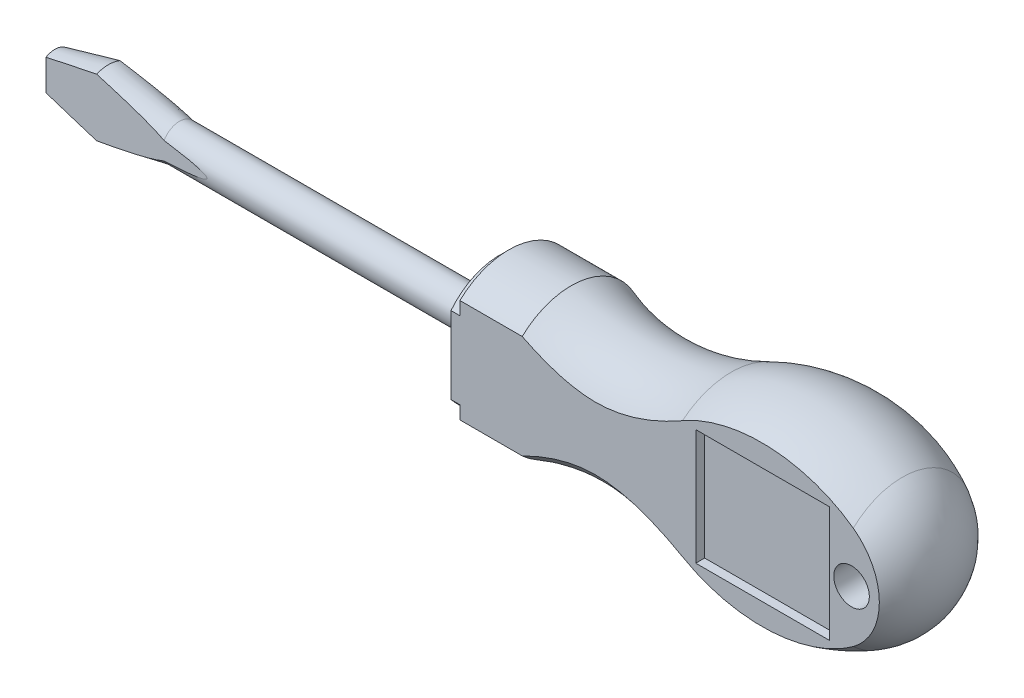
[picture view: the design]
ISO-10303-21;
HEADER;
FILE_DESCRIPTION(('STEP AP214'),'2;1');
FILE_NAME('part.step','',(''),(''),'','','');
FILE_SCHEMA(('AUTOMOTIVE_DESIGN { 1 0 10303 214 1 1 1 1 }'));
ENDSEC;
DATA;
#1=APPLICATION_CONTEXT('core data for automotive mechanical design processes');
#2=APPLICATION_PROTOCOL_DEFINITION('international standard','automotive_design',2000,#1);
#3=PRODUCT_CONTEXT('',#1,'mechanical');
#4=PRODUCT('Part','Part','',(#3));
#5=PRODUCT_RELATED_PRODUCT_CATEGORY('part','',(#4));
#6=PRODUCT_DEFINITION_FORMATION('','',#4);
#7=PRODUCT_DEFINITION_CONTEXT('part definition',#1,'design');
#8=PRODUCT_DEFINITION('design','',#6,#7);
#9=PRODUCT_DEFINITION_SHAPE('','',#8);
#10=(LENGTH_UNIT() NAMED_UNIT(*) SI_UNIT(.MILLI.,.METRE.));
#11=(NAMED_UNIT(*) PLANE_ANGLE_UNIT() SI_UNIT($,.RADIAN.));
#12=(NAMED_UNIT(*) SI_UNIT($,.STERADIAN.) SOLID_ANGLE_UNIT());
#13=UNCERTAINTY_MEASURE_WITH_UNIT(LENGTH_MEASURE(1.E-05),#10,'distance_accuracy_value','');
#14=(GEOMETRIC_REPRESENTATION_CONTEXT(3) GLOBAL_UNCERTAINTY_ASSIGNED_CONTEXT((#13)) GLOBAL_UNIT_ASSIGNED_CONTEXT((#10,
#11,#12)) REPRESENTATION_CONTEXT('',''));
#15=CARTESIAN_POINT('',(0.,0.,0.));
#16=DIRECTION('',(0.,0.,1.));
#17=DIRECTION('',(1.,0.,0.));
#18=AXIS2_PLACEMENT_3D('',#15,#16,#17);
#19=CARTESIAN_POINT('',(-86.,0.,0.));
#20=DIRECTION('',(-1.,0.,0.));
#21=DIRECTION('',(0.,-1.,0.));
#22=AXIS2_PLACEMENT_3D('',#19,#20,#21);
#23=CONICAL_SURFACE('',#22,2.,0.185347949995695);
#24=CARTESIAN_POINT('',(-85.9998,-0.997029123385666,-1.73371939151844));
#25=CARTESIAN_POINT('',(-86.0641111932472,-1.02705859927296,-1.73034898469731));
#26=CARTESIAN_POINT('',(-86.1288400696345,-1.05616798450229,-1.72695668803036));
#27=CARTESIAN_POINT('',(-86.2589632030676,-1.11282617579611,-1.72013722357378));
#28=CARTESIAN_POINT('',(-86.3243573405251,-1.14037525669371,-1.71671006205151));
#29=CARTESIAN_POINT('',(-86.5212414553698,-1.22108563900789,-1.70639180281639));
#30=CARTESIAN_POINT('',(-86.6535075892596,-1.27234401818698,-1.69946002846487));
#31=CARTESIAN_POINT('',(-86.9192182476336,-1.37111150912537,-1.68553472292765));
#32=CARTESIAN_POINT('',(-87.0526610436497,-1.4186253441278,-1.67854128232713));
#33=CARTESIAN_POINT('',(-87.3205297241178,-1.51085295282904,-1.66450287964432));
#34=CARTESIAN_POINT('',(-87.454955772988,-1.5555662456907,-1.65745790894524));
#35=CARTESIAN_POINT('',(-87.7242744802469,-1.64269849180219,-1.64334351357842));
#36=CARTESIAN_POINT('',(-87.8591658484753,-1.68512146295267,-1.63627415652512));
#37=CARTESIAN_POINT('',(-88.1294872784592,-1.76817316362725,-1.62210721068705));
#38=CARTESIAN_POINT('',(-88.2649173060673,-1.80880200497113,-1.61500962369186));
#39=CARTESIAN_POINT('',(-88.6719647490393,-1.92851287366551,-1.59367717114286));
#40=CARTESIAN_POINT('',(-88.9442298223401,-2.00538437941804,-1.57940836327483));
#41=CARTESIAN_POINT('',(-89.6123224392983,-2.18849639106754,-1.54439511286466));
#42=CARTESIAN_POINT('',(-90.0087736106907,-2.2924370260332,-1.52361798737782));
#43=CARTESIAN_POINT('',(-90.8030965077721,-2.49441785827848,-1.48198928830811));
#44=CARTESIAN_POINT('',(-91.2009680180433,-2.59245891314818,-1.46113772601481));
#45=CARTESIAN_POINT('',(-91.9986411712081,-2.78452833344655,-1.41933344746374));
#46=CARTESIAN_POINT('',(-92.3984451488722,-2.8785469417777,-1.39838060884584));
#47=CARTESIAN_POINT('',(-92.998711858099,-3.01718603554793,-1.36692196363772));
#48=CARTESIAN_POINT('',(-93.1989007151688,-3.06300237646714,-1.35643051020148));
#49=CARTESIAN_POINT('',(-93.5994368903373,-3.15392922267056,-1.33543929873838));
#50=CARTESIAN_POINT('',(-93.7997842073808,-3.1990397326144,-1.32493954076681));
#51=CARTESIAN_POINT('',(-94.0002,-3.24384339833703,-1.31443619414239));
#52=B_SPLINE_CURVE_WITH_KNOTS('',3,(#24,#25,#26,#27,#28,#29,#30,#31,#32,#33,#34,#35,#36,#37,#38,
#39,#40,#41,#42,#43,#44,#45,#46,#47,#48,#49,#50,#51),.UNSPECIFIED.,.F.,.F.,(4,2,2,2,2,2,2,2,2,2,
2,2,2,4),(0.,0.213148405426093,0.426259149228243,0.852235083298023,1.27766480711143,
1.70316737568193,2.12789746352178,2.55260104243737,3.40235387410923,4.63341377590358,
5.86429429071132,7.09800838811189,7.71490542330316,8.33179838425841),.UNSPECIFIED.);
#53=CARTESIAN_POINT('',(-86.,-0.997122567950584,-1.73370890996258));
#54=VERTEX_POINT('',#53);
#55=CARTESIAN_POINT('',(-94.,-3.24379868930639,-1.31444667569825));
#56=VERTEX_POINT('',#55);
#57=EDGE_CURVE('E267',#54,#56,#52,.T.);
#58=ORIENTED_EDGE('',*,*,#57,.F.);
#59=CARTESIAN_POINT('',(-86.,0.,0.));
#60=DIRECTION('',(1.,0.,0.));
#61=DIRECTION('',(0.,1.,0.));
#62=AXIS2_PLACEMENT_3D('',#59,#60,#61);
#63=CIRCLE('',#62,2.);
#64=CARTESIAN_POINT('',(-86.,-0.997122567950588,1.73370890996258));
#65=VERTEX_POINT('',#64);
#66=EDGE_CURVE('E347',#65,#54,#63,.T.);
#67=ORIENTED_EDGE('',*,*,#66,.F.);
#68=CARTESIAN_POINT('',(-94.0002,-3.24384339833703,1.31443619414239));
#69=CARTESIAN_POINT('',(-93.7596579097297,-3.19006455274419,1.32704247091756));
#70=CARTESIAN_POINT('',(-93.5192119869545,-3.13585064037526,1.33964370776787));
#71=CARTESIAN_POINT('',(-93.038553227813,-3.02637790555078,1.36483396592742));
#72=CARTESIAN_POINT('',(-92.7983403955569,-2.97111906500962,1.37742298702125));
#73=CARTESIAN_POINT('',(-92.3181143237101,-2.8593643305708,1.40259056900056));
#74=CARTESIAN_POINT('',(-92.0781011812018,-2.80286801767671,1.41516912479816));
#75=CARTESIAN_POINT('',(-91.5984216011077,-2.68842317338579,1.44030806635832));
#76=CARTESIAN_POINT('',(-91.3587551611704,-2.63047465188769,1.4528684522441));
#77=CARTESIAN_POINT('',(-90.8807458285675,-2.5130428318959,1.47791985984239));
#78=CARTESIAN_POINT('',(-90.6424013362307,-2.45356607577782,1.4904109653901));
#79=CARTESIAN_POINT('',(-90.1662557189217,-2.33247168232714,1.51536469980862));
#80=CARTESIAN_POINT('',(-89.9284545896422,-2.27085406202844,1.52782732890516));
#81=CARTESIAN_POINT('',(-89.4535670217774,-2.14492489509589,1.55271513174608));
#82=CARTESIAN_POINT('',(-89.216480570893,-2.08061339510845,1.56514030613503));
#83=CARTESIAN_POINT('',(-88.7432791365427,-1.94850747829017,1.58993974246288));
#84=CARTESIAN_POINT('',(-88.5071641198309,-1.88071318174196,1.60231400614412));
#85=CARTESIAN_POINT('',(-88.0790308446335,-1.75314065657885,1.62475152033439));
#86=CARTESIAN_POINT('',(-87.8867824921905,-1.69413893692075,1.63482682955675));
#87=CARTESIAN_POINT('',(-87.5036598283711,-1.57196725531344,1.65490543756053));
#88=CARTESIAN_POINT('',(-87.3127851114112,-1.50879858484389,1.66490875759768));
#89=CARTESIAN_POINT('',(-87.0278448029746,-1.40959258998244,1.67984184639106));
#90=CARTESIAN_POINT('',(-86.9330171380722,-1.37575256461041,1.68481155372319));
#91=CARTESIAN_POINT('',(-86.7440315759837,-1.30626984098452,1.69471586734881));
#92=CARTESIAN_POINT('',(-86.6498736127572,-1.27062732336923,1.69965047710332));
#93=CARTESIAN_POINT('',(-86.4623264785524,-1.19708852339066,1.7094794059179));
#94=CARTESIAN_POINT('',(-86.3689381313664,-1.15919011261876,1.71437368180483));
#95=CARTESIAN_POINT('',(-86.1833644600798,-1.08047106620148,1.72409918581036));
#96=CARTESIAN_POINT('',(-86.0911795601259,-1.03964943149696,1.72893039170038));
#97=CARTESIAN_POINT('',(-85.9998,-0.997029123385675,1.73371939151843));
#98=B_SPLINE_CURVE_WITH_KNOTS('',3,(#68,#69,#70,#71,#72,#73,#74,#75,#76,#77,#78,#79,#80,#81,#82,
#83,#84,#85,#86,#87,#88,#89,#90,#91,#92,#93,#94,#95,#96,#97),.UNSPECIFIED.,.F.,.F.,(4,2,2,2,2,2,
2,2,2,2,2,2,2,2,4),(0.,0.740408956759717,1.48083074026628,2.22150722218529,2.96217865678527,
3.70008308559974,4.4379816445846,5.17586743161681,5.91372775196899,6.51774967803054,
7.12158526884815,7.42399295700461,7.72637039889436,8.02903779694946,8.33180913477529),.UNSPECIFIED.);
#99=CARTESIAN_POINT('',(-94.,-3.24379868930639,1.31444667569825));
#100=VERTEX_POINT('',#99);
#101=EDGE_CURVE('E203',#100,#65,#98,.T.);
#102=ORIENTED_EDGE('',*,*,#101,.F.);
#103=CARTESIAN_POINT('',(-94.,0.,0.));
#104=DIRECTION('',(1.,0.,0.));
#105=DIRECTION('',(0.,1.,0.));
#106=AXIS2_PLACEMENT_3D('',#103,#104,#105);
#107=CIRCLE('',#106,3.5);
#108=EDGE_CURVE('E343',#100,#56,#107,.T.);
#109=ORIENTED_EDGE('',*,*,#108,.T.);
#110=EDGE_LOOP('',(#58,#67,#102,#109));
#111=FACE_BOUND('',#110,.T.);
#112=ADVANCED_FACE('F38',(#111),#23,.T.);
#113=CARTESIAN_POINT('',(-94.,0.,0.));
#114=DIRECTION('',(1.,0.,0.));
#115=DIRECTION('',(0.,1.,0.));
#116=AXIS2_PLACEMENT_3D('',#113,#114,#115);
#117=CONICAL_SURFACE('',#116,3.5,0.244978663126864);
#118=CARTESIAN_POINT('',(-93.9998,-3.24384839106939,-1.31445715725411));
#119=CARTESIAN_POINT('',(-94.5002347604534,-3.11946254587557,-1.2882304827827));
#120=CARTESIAN_POINT('',(-95.000625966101,-2.99489977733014,-1.26200609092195));
#121=CARTESIAN_POINT('',(-96.001246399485,-2.74513345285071,-1.20956579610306));
#122=CARTESIAN_POINT('',(-96.5014756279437,-2.61992989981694,-1.18334989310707));
#123=CARTESIAN_POINT('',(-97.501703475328,-2.36859351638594,-1.1309301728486));
#124=CARTESIAN_POINT('',(-98.0017020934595,-2.24246068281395,-1.10472635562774));
#125=CARTESIAN_POINT('',(-98.7514105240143,-2.05211247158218,-1.06543580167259));
#126=CARTESIAN_POINT('',(-99.0012656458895,-1.98847143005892,-1.05234144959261));
#127=CARTESIAN_POINT('',(-99.5008423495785,-1.86066442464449,-1.02615974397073));
#128=CARTESIAN_POINT('',(-99.7505639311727,-1.79649845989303,-1.01307239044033));
#129=CARTESIAN_POINT('',(-100.0002,-1.73199912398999,-0.999989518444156));
#130=B_SPLINE_CURVE_WITH_KNOTS('',3,(#118,#119,#120,#121,#122,#123,#124,#125,#126,#127,#128,
#129),.UNSPECIFIED.,.F.,.F.,(4,2,2,2,2,4),(0.,1.54898444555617,3.0979618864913,4.64694462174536,
5.42143947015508,6.19593558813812),.UNSPECIFIED.);
#131=CARTESIAN_POINT('',(-100.,-1.73205080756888,-0.999999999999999));
#132=VERTEX_POINT('',#131);
#133=EDGE_CURVE('E61',#56,#132,#130,.T.);
#134=ORIENTED_EDGE('',*,*,#133,.F.);
#135=ORIENTED_EDGE('',*,*,#108,.F.);
#136=CARTESIAN_POINT('',(-100.0002,-1.73199912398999,0.999989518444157));
#137=CARTESIAN_POINT('',(-99.7407971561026,-1.79902077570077,1.01358424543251));
#138=CARTESIAN_POINT('',(-99.4813023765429,-1.86568392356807,1.02718379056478));
#139=CARTESIAN_POINT('',(-98.9621702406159,-1.99844954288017,1.05439035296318));
#140=CARTESIAN_POINT('',(-98.7025328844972,-2.06455201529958,1.06799737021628));
#141=CARTESIAN_POINT('',(-97.9234699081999,-2.26225266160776,1.10882633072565));
#142=CARTESIAN_POINT('',(-97.4038910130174,-2.39324467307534,1.13605630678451));
#143=CARTESIAN_POINT('',(-96.403625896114,-2.64443239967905,1.1884779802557));
#144=CARTESIAN_POINT('',(-95.9229572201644,-2.7646983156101,1.21366875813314));
#145=CARTESIAN_POINT('',(-94.9614728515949,-3.00464833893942,1.26405801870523));
#146=CARTESIAN_POINT('',(-94.4806571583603,-3.12433244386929,1.28925650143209));
#147=CARTESIAN_POINT('',(-93.9998,-3.24384839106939,1.31445715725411));
#148=B_SPLINE_CURVE_WITH_KNOTS('',3,(#136,#137,#138,#139,#140,#141,#142,#143,#144,#145,#146,
#147),.UNSPECIFIED.,.F.,.F.,(4,2,2,2,2,4),(0.,0.804796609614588,1.60959181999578,
3.21917489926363,4.70755207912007,6.19593556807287),.UNSPECIFIED.);
#149=CARTESIAN_POINT('',(-100.,-1.73205080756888,1.));
#150=VERTEX_POINT('',#149);
#151=EDGE_CURVE('E192',#150,#100,#148,.T.);
#152=ORIENTED_EDGE('',*,*,#151,.F.);
#153=CARTESIAN_POINT('',(-100.,0.,0.));
#154=DIRECTION('',(1.,0.,0.));
#155=DIRECTION('',(0.,1.,0.));
#156=AXIS2_PLACEMENT_3D('',#153,#154,#155);
#157=CIRCLE('',#156,2.);
#158=EDGE_CURVE('E339',#150,#132,#157,.T.);
#159=ORIENTED_EDGE('',*,*,#158,.T.);
#160=EDGE_LOOP('',(#134,#135,#152,#159));
#161=FACE_BOUND('',#160,.T.);
#162=ADVANCED_FACE('F382',(#161),#117,.T.);
#163=CARTESIAN_POINT('',(-9.,0.,0.));
#164=DIRECTION('',(1.,0.,0.));
#165=DIRECTION('',(0.,-1.,0.));
#166=AXIS2_PLACEMENT_3D('',#163,#164,#165);
#167=SPHERICAL_SURFACE('',#166,9.);
#168=CARTESIAN_POINT('',(-4.80330765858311,1.9903045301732,-7.70885602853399));
#169=CARTESIAN_POINT('',(-4.67987699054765,1.97812861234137,-7.64484422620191));
#170=CARTESIAN_POINT('',(-4.5576421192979,1.9544311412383,-7.58058776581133));
#171=CARTESIAN_POINT('',(-4.31850956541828,1.88444434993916,-7.4533214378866));
#172=CARTESIAN_POINT('',(-4.20163401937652,1.83806920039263,-7.39031726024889));
#173=CARTESIAN_POINT('',(-3.97697916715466,1.72318761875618,-7.26771163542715));
#174=CARTESIAN_POINT('',(-3.8692147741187,1.65464575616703,-7.20811581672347));
#175=CARTESIAN_POINT('',(-3.66690742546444,1.49643441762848,-7.09495921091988));
#176=CARTESIAN_POINT('',(-3.57234823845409,1.40679124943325,-7.04139103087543));
#177=CARTESIAN_POINT('',(-3.40676376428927,1.21510191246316,-6.94666826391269));
#178=CARTESIAN_POINT('',(-3.33453799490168,1.11440391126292,-6.90489938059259));
#179=CARTESIAN_POINT('',(-3.20885866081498,0.898527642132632,-6.83170669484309));
#180=CARTESIAN_POINT('',(-3.15538353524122,0.783366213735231,-6.80027101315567));
#181=CARTESIAN_POINT('',(-3.07673416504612,0.559534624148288,-6.75383883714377));
#182=CARTESIAN_POINT('',(-3.04862965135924,0.452244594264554,-6.73714768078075));
#183=CARTESIAN_POINT('',(-3.01057498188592,0.233417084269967,-6.71451668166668));
#184=CARTESIAN_POINT('',(-3.0006079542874,0.121883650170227,-6.70856684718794));
#185=CARTESIAN_POINT('',(-2.99951148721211,-0.0885410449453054,-6.70791228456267));
#186=CARTESIAN_POINT('',(-3.00636627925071,-0.187425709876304,-6.71200424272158));
#187=CARTESIAN_POINT('',(-3.03442671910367,-0.382381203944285,-6.72870585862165));
#188=CARTESIAN_POINT('',(-3.05563115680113,-0.478452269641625,-6.7413147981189));
#189=CARTESIAN_POINT('',(-3.11107629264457,-0.66429396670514,-6.77413263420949));
#190=CARTESIAN_POINT('',(-3.14518792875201,-0.754116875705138,-6.79426626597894));
#191=CARTESIAN_POINT('',(-3.22503287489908,-0.926568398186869,-6.84111172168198));
#192=CARTESIAN_POINT('',(-3.27076935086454,-1.00919504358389,-6.86782533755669));
#193=CARTESIAN_POINT('',(-3.37666625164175,-1.17263374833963,-6.92923867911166));
#194=CARTESIAN_POINT('',(-3.43773100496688,-1.25267340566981,-6.96442874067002));
#195=CARTESIAN_POINT('',(-3.56969281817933,-1.40147200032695,-7.03981280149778));
#196=CARTESIAN_POINT('',(-3.64059436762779,-1.4702257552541,-7.08000908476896));
#197=CARTESIAN_POINT('',(-3.80012285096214,-1.60389738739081,-7.16960509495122));
#198=CARTESIAN_POINT('',(-3.88985563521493,-1.66714830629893,-7.21952158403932));
#199=CARTESIAN_POINT('',(-4.07706172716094,-1.77764123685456,-7.32250983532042));
#200=CARTESIAN_POINT('',(-4.1745390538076,-1.82487486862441,-7.37558323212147));
#201=CARTESIAN_POINT('',(-4.35986983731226,-1.89699324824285,-7.4753631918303));
#202=CARTESIAN_POINT('',(-4.44697267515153,-1.92416797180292,-7.52183016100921));
#203=CARTESIAN_POINT('',(-4.62360194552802,-1.96635493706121,-7.61518387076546));
#204=CARTESIAN_POINT('',(-4.71312258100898,-1.98139399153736,-7.66206945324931));
#205=CARTESIAN_POINT('',(-4.80330765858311,-1.9903045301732,-7.70885602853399));
#206=B_SPLINE_CURVE_WITH_KNOTS('',3,(#168,#169,#170,#171,#172,#173,#174,#175,#176,#177,#178,
#179,#180,#181,#182,#183,#184,#185,#186,#187,#188,#189,#190,#191,#192,#193,#194,#195,#196,#197,
#198,#199,#200,#201,#202,#203,#204,#205),.UNSPECIFIED.,.F.,.F.,(4,2,2,2,2,2,2,2,2,2,2,2,2,2,2,2,
2,2,4),(0.,0.418354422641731,0.838304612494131,1.25892938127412,1.67903249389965,
2.06904704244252,2.45861164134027,2.79315963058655,3.1273962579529,3.42357399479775,
3.71972675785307,4.01299329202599,4.30633978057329,4.62500983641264,4.94382581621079,
5.30418111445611,5.66472465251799,5.97116902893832,6.2769344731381),.UNSPECIFIED.);
#207=CARTESIAN_POINT('',(-4.8031076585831,1.99028475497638,-7.70875225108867));
#208=VERTEX_POINT('',#207);
#209=CARTESIAN_POINT('',(-4.80310765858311,-1.99028475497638,-7.70875225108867));
#210=VERTEX_POINT('',#209);
#211=EDGE_CURVE('E287',#208,#210,#206,.T.);
#212=ORIENTED_EDGE('',*,*,#211,.F.);
#213=CARTESIAN_POINT('',(-4.80310765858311,0.,0.));
#214=DIRECTION('',(1.,0.,0.));
#215=DIRECTION('',(0.,1.,0.));
#216=AXIS2_PLACEMENT_3D('',#213,#214,#215);
#217=CIRCLE('',#216,7.96153846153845);
#218=CARTESIAN_POINT('',(-4.80310765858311,5.75639597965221,5.50000000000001));
#219=VERTEX_POINT('',#218);
#220=EDGE_CURVE('E366',#208,#219,#217,.T.);
#221=ORIENTED_EDGE('',*,*,#220,.T.);
#222=CARTESIAN_POINT('',(-9.,0.,5.50000000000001));
#223=DIRECTION('',(0.,0.,-1.));
#224=DIRECTION('',(-1.,0.,0.));
#225=AXIS2_PLACEMENT_3D('',#222,#223,#224);
#226=CIRCLE('',#225,7.1239034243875);
#227=CARTESIAN_POINT('',(-4.8031076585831,-5.75639597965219,5.50000000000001));
#228=VERTEX_POINT('',#227);
#229=EDGE_CURVE('E309',#228,#219,#226,.F.);
#230=ORIENTED_EDGE('',*,*,#229,.F.);
#231=EDGE_CURVE('E367',#228,#210,#217,.T.);
#232=ORIENTED_EDGE('',*,*,#231,.T.);
#233=EDGE_LOOP('',(#212,#221,#230,#232));
#234=FACE_BOUND('',#233,.T.);
#235=ADVANCED_FACE('F40',(#234),#167,.T.);
#236=CARTESIAN_POINT('',(-15.0621778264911,0.,0.));
#237=DIRECTION('',(1.,0.,0.));
#238=DIRECTION('',(0.,1.,0.));
#239=AXIS2_PLACEMENT_3D('',#236,#237,#238);
#240=DEGENERATE_TOROIDAL_SURFACE('',#239,11.5,22.,.F.);
#241=CARTESIAN_POINT('',(-4.80290765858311,-1.99026495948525,-7.70864847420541));
#242=CARTESIAN_POINT('',(-4.93039350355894,-2.00287079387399,-7.7747636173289));
#243=CARTESIAN_POINT('',(-5.05810757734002,-2.00317192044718,-7.84260432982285));
#244=CARTESIAN_POINT('',(-5.31090760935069,-1.97977019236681,-7.97950600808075));
#245=CARTESIAN_POINT('',(-5.43598940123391,-1.95603183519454,-8.04856863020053));
#246=CARTESIAN_POINT('',(-5.68004785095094,-1.88512174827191,-8.18547613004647));
#247=CARTESIAN_POINT('',(-5.79902430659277,-1.83794924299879,-8.25332096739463));
#248=CARTESIAN_POINT('',(-6.02747074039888,-1.72069036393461,-8.38522576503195));
#249=CARTESIAN_POINT('',(-6.13694262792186,-1.65060860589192,-8.44928648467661));
#250=CARTESIAN_POINT('',(-6.33950166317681,-1.49060737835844,-8.56896216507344));
#251=CARTESIAN_POINT('',(-6.43296987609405,-1.40131732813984,-8.6247672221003));
#252=CARTESIAN_POINT('',(-6.60290209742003,-1.20319442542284,-8.72692036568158));
#253=CARTESIAN_POINT('',(-6.67938491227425,-1.09438343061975,-8.77327890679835));
#254=CARTESIAN_POINT('',(-6.80177168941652,-0.87586283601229,-8.84779506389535));
#255=CARTESIAN_POINT('',(-6.85040259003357,-0.768235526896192,-8.87756073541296));
#256=CARTESIAN_POINT('',(-6.92830335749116,-0.543778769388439,-8.92534936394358));
#257=CARTESIAN_POINT('',(-6.95760071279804,-0.426962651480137,-8.94338899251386));
#258=CARTESIAN_POINT('',(-6.99191512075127,-0.206794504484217,-8.96453132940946));
#259=CARTESIAN_POINT('',(-6.99993416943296,-0.104078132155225,-8.96948045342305));
#260=CARTESIAN_POINT('',(-7.00006490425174,0.101353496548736,-8.96956091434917));
#261=CARTESIAN_POINT('',(-6.99218300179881,0.204068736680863,-8.96469620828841));
#262=CARTESIAN_POINT('',(-6.96200565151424,0.399614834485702,-8.94610318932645));
#263=CARTESIAN_POINT('',(-6.94067586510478,0.492655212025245,-8.93296878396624));
#264=CARTESIAN_POINT('',(-6.88556171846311,0.673494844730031,-8.89911777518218));
#265=CARTESIAN_POINT('',(-6.85177600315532,0.761293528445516,-8.87840034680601));
#266=CARTESIAN_POINT('',(-6.7713163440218,0.933764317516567,-8.82923636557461));
#267=CARTESIAN_POINT('',(-6.72411289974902,1.01809741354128,-8.80047326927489));
#268=CARTESIAN_POINT('',(-6.61939050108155,1.17757674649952,-8.7369658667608));
#269=CARTESIAN_POINT('',(-6.5618675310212,1.25271938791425,-8.70221923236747));
#270=CARTESIAN_POINT('',(-6.43071927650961,1.40143830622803,-8.62346397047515));
#271=CARTESIAN_POINT('',(-6.35598633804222,1.47371132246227,-8.57884279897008));
#272=CARTESIAN_POINT('',(-6.19795808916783,1.60482207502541,-8.48524841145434));
#273=CARTESIAN_POINT('',(-6.11465749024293,1.66365144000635,-8.43627250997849));
#274=CARTESIAN_POINT('',(-5.92896226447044,1.77492807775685,-8.32814505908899));
#275=CARTESIAN_POINT('',(-5.82554564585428,1.8252353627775,-8.26854396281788));
#276=CARTESIAN_POINT('',(-5.61262990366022,1.90727734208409,-8.14746470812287));
#277=CARTESIAN_POINT('',(-5.50312941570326,1.93900785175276,-8.08598613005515));
#278=CARTESIAN_POINT('',(-5.29532642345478,1.98051995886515,-7.97115535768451));
#279=CARTESIAN_POINT('',(-5.197483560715,1.99266848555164,-7.91781536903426));
#280=CARTESIAN_POINT('',(-5.00068300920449,2.00241975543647,-7.8121934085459));
#281=CARTESIAN_POINT('',(-4.90172696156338,2.00004166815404,-7.7599101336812));
#282=CARTESIAN_POINT('',(-4.80290765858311,1.99026495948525,-7.70864847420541));
#283=B_SPLINE_CURVE_WITH_KNOTS('',3,(#241,#242,#243,#244,#245,#246,#247,#248,#249,#250,#251,
#252,#253,#254,#255,#256,#257,#258,#259,#260,#261,#262,#263,#264,#265,#266,#267,#268,#269,#270,
#271,#272,#273,#274,#275,#276,#277,#278,#279,#280,#281,#282),.UNSPECIFIED.,.F.,.F.,(4,2,2,2,2,2,
2,2,2,2,2,2,2,2,2,2,2,2,2,2,4),(0.,0.431852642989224,0.864343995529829,1.29684966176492,
1.72926824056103,2.14923380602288,2.56873203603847,2.93190502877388,3.29456054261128,
3.60236857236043,3.91005251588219,4.19782710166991,4.48563300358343,4.78691799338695,
5.08832047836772,5.42639916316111,5.76468779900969,6.15170567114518,6.53881068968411,
6.87417228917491,7.20909143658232),.UNSPECIFIED.);
#284=EDGE_CURVE('E281',#210,#208,#283,.T.);
#285=ORIENTED_EDGE('',*,*,#284,.F.);
#286=ORIENTED_EDGE('',*,*,#231,.F.);
#287=CARTESIAN_POINT('',(-1.09793778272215,0.,5.50000000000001));
#288=CARTESIAN_POINT('',(-1.09794053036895,0.143185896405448,5.50000000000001));
#289=CARTESIAN_POINT('',(-1.10476981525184,0.28639114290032,5.50000000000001));
#290=CARTESIAN_POINT('',(-1.13182268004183,0.571530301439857,5.50000000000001));
#291=CARTESIAN_POINT('',(-1.15204857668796,0.713463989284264,5.50000000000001));
#292=CARTESIAN_POINT('',(-1.20518507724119,0.995134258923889,5.50000000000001));
#293=CARTESIAN_POINT('',(-1.23811359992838,1.13486744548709,5.50000000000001));
#294=CARTESIAN_POINT('',(-1.31557543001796,1.41110185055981,5.50000000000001));
#295=CARTESIAN_POINT('',(-1.36011544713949,1.54760115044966,5.50000000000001));
#296=CARTESIAN_POINT('',(-1.53928463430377,2.03233731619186,5.50000000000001));
#297=CARTESIAN_POINT('',(-1.7040010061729,2.36977447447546,5.50000000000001));
#298=CARTESIAN_POINT('',(-1.98827681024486,2.85309050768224,5.50000000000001));
#299=CARTESIAN_POINT('',(-2.08942533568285,3.01062036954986,5.50000000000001));
#300=CARTESIAN_POINT('',(-2.3023289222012,3.31839314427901,5.50000000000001));
#301=CARTESIAN_POINT('',(-2.41408262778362,3.46863698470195,5.50000000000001));
#302=CARTESIAN_POINT('',(-2.72272990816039,3.85810294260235,5.50000000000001));
#303=CARTESIAN_POINT('',(-2.92743437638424,4.09112883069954,5.50000000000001));
#304=CARTESIAN_POINT('',(-3.35607613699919,4.5388088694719,5.50000000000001));
#305=CARTESIAN_POINT('',(-3.58002525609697,4.75345155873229,5.50000000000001));
#306=CARTESIAN_POINT('',(-4.04375211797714,5.16552977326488,5.50000000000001));
#307=CARTESIAN_POINT('',(-4.2835524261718,5.36293979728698,5.50000000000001));
#308=CARTESIAN_POINT('',(-4.7759716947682,5.74090055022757,5.50000000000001));
#309=CARTESIAN_POINT('',(-5.02858934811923,5.9214529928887,5.50000000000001));
#310=CARTESIAN_POINT('',(-5.66836726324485,6.34892277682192,5.50000000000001));
#311=CARTESIAN_POINT('',(-6.06200298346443,6.58619324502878,5.50000000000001));
#312=CARTESIAN_POINT('',(-6.86818306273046,7.02621879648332,5.50000000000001));
#313=CARTESIAN_POINT('',(-7.2807354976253,7.22895896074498,5.50000000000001));
#314=CARTESIAN_POINT('',(-8.12090875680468,7.60039402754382,5.50000000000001));
#315=CARTESIAN_POINT('',(-8.54853106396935,7.76908556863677,5.50000000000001));
#316=CARTESIAN_POINT('',(-9.41552557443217,8.07261652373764,5.50000000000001));
#317=CARTESIAN_POINT('',(-9.85489623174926,8.20746036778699,5.50000000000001));
#318=CARTESIAN_POINT('',(-10.7514541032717,8.44576989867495,5.50000000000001));
#319=CARTESIAN_POINT('',(-11.2088218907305,8.54855545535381,5.50000000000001));
#320=CARTESIAN_POINT('',(-12.1301733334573,8.7190629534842,5.50000000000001));
#321=CARTESIAN_POINT('',(-12.594158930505,8.78677437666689,5.50000000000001));
#322=CARTESIAN_POINT('',(-13.5258412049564,8.88706009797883,5.50000000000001));
#323=CARTESIAN_POINT('',(-13.9935373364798,8.91963947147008,5.50000000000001));
#324=CARTESIAN_POINT('',(-14.9300795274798,8.94966440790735,5.50000000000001));
#325=CARTESIAN_POINT('',(-15.3989256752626,8.94710718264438,5.50000000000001));
#326=CARTESIAN_POINT('',(-16.3886802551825,8.90454698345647,5.50000000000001));
#327=CARTESIAN_POINT('',(-16.909411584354,8.86029564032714,5.50000000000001));
#328=CARTESIAN_POINT('',(-17.945152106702,8.72819706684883,5.50000000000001));
#329=CARTESIAN_POINT('',(-18.4601630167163,8.64036329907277,5.50000000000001));
#330=CARTESIAN_POINT('',(-19.4811801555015,8.42106121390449,5.50000000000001));
#331=CARTESIAN_POINT('',(-19.987180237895,8.28956423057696,5.50000000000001));
#332=CARTESIAN_POINT('',(-20.9857023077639,7.98292860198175,5.50000000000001));
#333=CARTESIAN_POINT('',(-21.4782282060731,7.80780277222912,5.50000000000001));
#334=CARTESIAN_POINT('',(-22.3338554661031,7.45913765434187,5.50000000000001));
#335=CARTESIAN_POINT('',(-22.7006202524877,7.29453788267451,5.50000000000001));
#336=CARTESIAN_POINT('',(-23.4212896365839,6.93906334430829,5.50000000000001));
#337=CARTESIAN_POINT('',(-23.7751933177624,6.74818670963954,5.50000000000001));
#338=CARTESIAN_POINT('',(-24.4666049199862,6.34007755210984,5.50000000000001));
#339=CARTESIAN_POINT('',(-24.8041422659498,6.12289498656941,5.50000000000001));
#340=CARTESIAN_POINT('',(-25.4598504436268,5.66111521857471,5.50000000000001));
#341=CARTESIAN_POINT('',(-25.7780315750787,5.41653279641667,5.50000000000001));
#342=CARTESIAN_POINT('',(-26.256493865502,5.01160874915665,5.50000000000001));
#343=CARTESIAN_POINT('',(-26.4251114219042,4.86105712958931,5.50000000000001));
#344=CARTESIAN_POINT('',(-26.7533516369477,4.55046817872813,5.50000000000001));
#345=CARTESIAN_POINT('',(-26.9129764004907,4.39043308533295,5.50000000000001));
#346=CARTESIAN_POINT('',(-27.221637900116,4.06051360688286,5.50000000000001));
#347=CARTESIAN_POINT('',(-27.3706777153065,3.89063211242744,5.50000000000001));
#348=CARTESIAN_POINT('',(-27.6561388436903,3.54056092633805,5.50000000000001));
#349=CARTESIAN_POINT('',(-27.7925633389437,3.36037385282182,5.50000000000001));
#350=CARTESIAN_POINT('',(-28.0167913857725,3.03726706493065,5.50000000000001));
#351=CARTESIAN_POINT('',(-28.1080506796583,2.89674551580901,5.50000000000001));
#352=CARTESIAN_POINT('',(-28.2807412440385,2.60971862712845,5.50000000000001));
#353=CARTESIAN_POINT('',(-28.3621711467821,2.46321245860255,5.50000000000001));
#354=CARTESIAN_POINT('',(-28.5133884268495,2.16458475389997,5.50000000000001));
#355=CARTESIAN_POINT('',(-28.5831952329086,2.01247311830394,5.50000000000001));
#356=CARTESIAN_POINT('',(-28.7094229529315,1.70280721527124,5.50000000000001));
#357=CARTESIAN_POINT('',(-28.7658497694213,1.54525538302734,5.50000000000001));
#358=CARTESIAN_POINT('',(-28.853127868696,1.25908896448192,5.50000000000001));
#359=CARTESIAN_POINT('',(-28.8868619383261,1.13135253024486,5.50000000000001));
#360=CARTESIAN_POINT('',(-28.9438755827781,0.873610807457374,5.50000000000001));
#361=CARTESIAN_POINT('',(-28.9671603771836,0.743606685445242,5.50000000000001));
#362=CARTESIAN_POINT('',(-29.0025794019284,0.482182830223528,5.50000000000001));
#363=CARTESIAN_POINT('',(-29.0147225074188,0.350764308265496,5.50000000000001));
#364=CARTESIAN_POINT('',(-29.0274920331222,0.0873619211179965,5.50000000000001));
#365=CARTESIAN_POINT('',(-29.0281182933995,-0.0446219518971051,5.50000000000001));
#366=CARTESIAN_POINT('',(-29.0178311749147,-0.308153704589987,5.50000000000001));
#367=CARTESIAN_POINT('',(-29.0069162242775,-0.439701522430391,5.50000000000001));
#368=CARTESIAN_POINT('',(-28.9739066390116,-0.701372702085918,5.50000000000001));
#369=CARTESIAN_POINT('',(-28.9518120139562,-0.831496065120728,5.50000000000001));
#370=CARTESIAN_POINT('',(-28.8970854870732,-1.08963404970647,5.50000000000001));
#371=CARTESIAN_POINT('',(-28.8644431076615,-1.21764644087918,5.50000000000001));
#372=CARTESIAN_POINT('',(-28.7895029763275,-1.47083268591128,5.50000000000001));
#373=CARTESIAN_POINT('',(-28.7472002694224,-1.59600504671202,5.50000000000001));
#374=CARTESIAN_POINT('',(-28.5671961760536,-2.07255000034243,5.50000000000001));
#375=CARTESIAN_POINT('',(-28.3981833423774,-2.41246063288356,5.50000000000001));
#376=CARTESIAN_POINT('',(-28.1072496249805,-2.89903362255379,5.50000000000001));
#377=CARTESIAN_POINT('',(-28.0038200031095,-3.0576018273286,5.50000000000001));
#378=CARTESIAN_POINT('',(-27.786302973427,-3.36730008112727,5.50000000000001));
#379=CARTESIAN_POINT('',(-27.6722172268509,-3.5184312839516,5.50000000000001));
#380=CARTESIAN_POINT('',(-27.3572597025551,-3.91016187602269,5.50000000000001));
#381=CARTESIAN_POINT('',(-27.1485361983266,-4.14444166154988,5.50000000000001));
#382=CARTESIAN_POINT('',(-26.7117680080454,-4.59429000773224,5.50000000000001));
#383=CARTESIAN_POINT('',(-26.4837113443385,-4.809846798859,5.50000000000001));
#384=CARTESIAN_POINT('',(-26.0117069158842,-5.22341302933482,5.50000000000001));
#385=CARTESIAN_POINT('',(-25.7677374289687,-5.42139757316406,5.50000000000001));
#386=CARTESIAN_POINT('',(-25.2669234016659,-5.80018191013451,5.50000000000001));
#387=CARTESIAN_POINT('',(-25.0100801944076,-5.98098347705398,5.50000000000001));
#388=CARTESIAN_POINT('',(-24.3620538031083,-6.40716080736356,5.50000000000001));
#389=CARTESIAN_POINT('',(-23.9645083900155,-6.64290714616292,5.50000000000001));
#390=CARTESIAN_POINT('',(-23.1506537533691,-7.07955631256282,5.50000000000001));
#391=CARTESIAN_POINT('',(-22.7343366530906,-7.28044433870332,5.50000000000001));
#392=CARTESIAN_POINT('',(-21.8867894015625,-7.6478183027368,5.50000000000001));
#393=CARTESIAN_POINT('',(-21.4555582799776,-7.81430199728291,5.50000000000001));
#394=CARTESIAN_POINT('',(-20.5815009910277,-8.11305412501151,5.50000000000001));
#395=CARTESIAN_POINT('',(-20.1386763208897,-8.24532695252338,5.50000000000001));
#396=CARTESIAN_POINT('',(-19.2357482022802,-8.47795614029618,5.50000000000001));
#397=CARTESIAN_POINT('',(-18.7754763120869,-8.57765795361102,5.50000000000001));
#398=CARTESIAN_POINT('',(-17.8485419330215,-8.74167002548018,5.50000000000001));
#399=CARTESIAN_POINT('',(-17.3818775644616,-8.80596963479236,5.50000000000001));
#400=CARTESIAN_POINT('',(-16.4450739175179,-8.89910581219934,5.50000000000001));
#401=CARTESIAN_POINT('',(-15.9749349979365,-8.92794599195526,5.50000000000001));
#402=CARTESIAN_POINT('',(-15.0337956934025,-8.95016232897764,5.50000000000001));
#403=CARTESIAN_POINT('',(-14.5627952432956,-8.94353568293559,5.50000000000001));
#404=CARTESIAN_POINT('',(-13.5707624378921,-8.89212467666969,5.50000000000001));
#405=CARTESIAN_POINT('',(-13.049938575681,-8.84321433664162,5.50000000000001));
#406=CARTESIAN_POINT('',(-12.0144224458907,-8.70171856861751,5.50000000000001));
#407=CARTESIAN_POINT('',(-11.4997283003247,-8.60914688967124,5.50000000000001));
#408=CARTESIAN_POINT('',(-10.4798186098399,-8.38029037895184,5.50000000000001));
#409=CARTESIAN_POINT('',(-9.97460878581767,-8.24398000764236,5.50000000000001));
#410=CARTESIAN_POINT('',(-8.9781518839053,-7.92762861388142,5.50000000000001));
#411=CARTESIAN_POINT('',(-8.48690054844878,-7.74760108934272,5.50000000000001));
#412=CARTESIAN_POINT('',(-7.63958555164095,-7.3924867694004,5.50000000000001));
#413=CARTESIAN_POINT('',(-7.27957995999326,-7.22675052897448,5.50000000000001));
#414=CARTESIAN_POINT('',(-6.57238829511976,-6.86969270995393,5.50000000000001));
#415=CARTESIAN_POINT('',(-6.22520307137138,-6.67836943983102,5.50000000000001));
#416=CARTESIAN_POINT('',(-5.54711975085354,-6.27003918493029,5.50000000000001));
#417=CARTESIAN_POINT('',(-5.21619273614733,-6.05308032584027,5.50000000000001));
#418=CARTESIAN_POINT('',(-4.57357386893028,-5.59241001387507,5.50000000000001));
#419=CARTESIAN_POINT('',(-4.26187183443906,-5.34871291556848,5.50000000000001));
#420=CARTESIAN_POINT('',(-3.79300125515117,-4.94534383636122,5.50000000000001));
#421=CARTESIAN_POINT('',(-3.62757402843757,-4.79521428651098,5.50000000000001));
#422=CARTESIAN_POINT('',(-3.30570051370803,-4.48564335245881,5.50000000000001));
#423=CARTESIAN_POINT('',(-3.14925194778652,-4.32620435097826,5.50000000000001));
#424=CARTESIAN_POINT('',(-2.84691828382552,-3.99764811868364,5.50000000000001));
#425=CARTESIAN_POINT('',(-2.70103054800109,-3.82853332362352,5.50000000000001));
#426=CARTESIAN_POINT('',(-2.4218550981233,-3.48018924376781,5.50000000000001));
#427=CARTESIAN_POINT('',(-2.28856408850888,-3.30096262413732,5.50000000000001));
#428=CARTESIAN_POINT('',(-2.06963565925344,-2.97953340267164,5.50000000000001));
#429=CARTESIAN_POINT('',(-1.98056182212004,-2.83967135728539,5.50000000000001));
#430=CARTESIAN_POINT('',(-1.8122482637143,-2.55410351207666,5.50000000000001));
#431=CARTESIAN_POINT('',(-1.73300874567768,-2.40839759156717,5.50000000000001));
#432=CARTESIAN_POINT('',(-1.58617028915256,-2.11157763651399,5.50000000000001));
#433=CARTESIAN_POINT('',(-1.51854747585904,-1.96047548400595,5.50000000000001));
#434=CARTESIAN_POINT('',(-1.39660482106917,-1.65299544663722,5.50000000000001));
#435=CARTESIAN_POINT('',(-1.34227966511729,-1.49661969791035,5.50000000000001));
#436=CARTESIAN_POINT('',(-1.26356627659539,-1.2294920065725,5.50000000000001));
#437=CARTESIAN_POINT('',(-1.23514124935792,-1.11992076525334,5.50000000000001));
#438=CARTESIAN_POINT('',(-1.18594868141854,-0.899079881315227,5.50000000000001));
#439=CARTESIAN_POINT('',(-1.16517960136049,-0.787810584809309,5.50000000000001));
#440=CARTESIAN_POINT('',(-1.13175634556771,-0.56408764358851,5.50000000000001));
#441=CARTESIAN_POINT('',(-1.11909967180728,-0.451634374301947,5.50000000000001));
#442=CARTESIAN_POINT('',(-1.10219023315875,-0.226124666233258,5.50000000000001));
#443=CARTESIAN_POINT('',(-1.09793561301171,-0.113068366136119,5.50000000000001));
#444=CARTESIAN_POINT('',(-1.09793778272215,0.,5.50000000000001));
#445=B_SPLINE_CURVE_WITH_KNOTS('',3,(#287,#288,#289,#290,#291,#292,#293,#294,#295,#296,#297,
#298,#299,#300,#301,#302,#303,#304,#305,#306,#307,#308,#309,#310,#311,#312,#313,#314,#315,#316,
#317,#318,#319,#320,#321,#322,#323,#324,#325,#326,#327,#328,#329,#330,#331,#332,#333,#334,#335,
#336,#337,#338,#339,#340,#341,#342,#343,#344,#345,#346,#347,#348,#349,#350,#351,#352,#353,#354,
#355,#356,#357,#358,#359,#360,#361,#362,#363,#364,#365,#366,#367,#368,#369,#370,#371,#372,#373,
#374,#375,#376,#377,#378,#379,#380,#381,#382,#383,#384,#385,#386,#387,#388,#389,#390,#391,#392,
#393,#394,#395,#396,#397,#398,#399,#400,#401,#402,#403,#404,#405,#406,#407,#408,#409,#410,#411,
#412,#413,#414,#415,#416,#417,#418,#419,#420,#421,#422,#423,#424,#425,#426,#427,#428,#429,#430,
#431,#432,#433,#434,#435,#436,#437,#438,#439,#440,#441,#442,#443,#444),.UNSPECIFIED.,.T.,.F.,(4,
2,2,2,2,2,2,2,2,2,2,2,2,2,2,2,2,2,2,2,2,2,2,2,2,2,2,2,2,2,2,2,2,2,2,2,2,2,2,2,2,2,2,2,2,2,2,2,2,
2,2,2,2,2,2,2,2,2,2,2,2,2,2,2,2,2,2,2,2,2,2,2,2,2,2,2,2,2,4),(0.,0.429431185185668,
0.858936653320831,1.2890502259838,1.71941289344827,2.83862650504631,3.4000131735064,
3.96132818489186,4.89040151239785,5.82004993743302,6.75105154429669,7.68195840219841,
9.05885282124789,10.43634063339,11.8139643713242,13.1914077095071,14.5963485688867,
16.0017105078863,17.4068693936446,18.812139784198,20.3780984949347,21.9435737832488,
23.510078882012,25.0761243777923,26.2811818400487,27.4863250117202,28.6892143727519,
29.8914579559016,30.569291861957,31.2469664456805,31.9244430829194,32.6017483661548,
33.1040760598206,33.6064735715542,34.1080226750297,34.6093501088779,35.0053054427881,
35.401062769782,35.7965045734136,36.1919518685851,36.5874530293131,36.9829538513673,
37.378848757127,37.7749471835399,38.9063767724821,39.4741007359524,40.0417363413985,
40.9816028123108,41.9220558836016,42.8638207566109,43.8054883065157,45.1900988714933,
46.5752959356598,47.9605832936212,49.3456926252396,50.7571334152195,52.1689985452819,
53.5807198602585,54.9925527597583,56.5600263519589,58.1270066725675,59.6949036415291,
61.2623171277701,62.4503578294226,63.6384771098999,64.8244003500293,66.0096900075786,
66.6795660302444,67.3492713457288,68.0188088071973,68.6881706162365,69.1852881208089,
69.6824158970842,70.1785094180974,70.6744043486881,71.0137572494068,71.3530418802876,
71.6922219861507,72.0313271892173),.UNSPECIFIED.);
#446=CARTESIAN_POINT('',(-23.9971410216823,-6.61641444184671,5.50000000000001));
#447=VERTEX_POINT('',#446);
#448=EDGE_CURVE('E303',#447,#228,#445,.T.);
#449=ORIENTED_EDGE('',*,*,#448,.F.);
#450=CARTESIAN_POINT('',(-23.9971410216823,0.,0.));
#451=DIRECTION('',(1.,0.,0.));
#452=DIRECTION('',(0.,1.,0.));
#453=AXIS2_PLACEMENT_3D('',#450,#451,#452);
#454=CIRCLE('',#453,8.60389098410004);
#455=CARTESIAN_POINT('',(-23.9971410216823,6.61641444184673,5.50000000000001));
#456=VERTEX_POINT('',#455);
#457=EDGE_CURVE('E363',#447,#456,#454,.T.);
#458=ORIENTED_EDGE('',*,*,#457,.T.);
#459=EDGE_CURVE('E311',#219,#456,#445,.T.);
#460=ORIENTED_EDGE('',*,*,#459,.F.);
#461=ORIENTED_EDGE('',*,*,#220,.F.);
#462=EDGE_LOOP('',(#285,#286,#449,#458,#460,#461));
#463=FACE_BOUND('',#462,.T.);
#464=ADVANCED_FACE('F293',(#463),#240,.F.);
#465=CARTESIAN_POINT('',(-33.7443735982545,0.,0.));
#466=DIRECTION('',(1.,0.,0.));
#467=DIRECTION('',(0.,1.,0.));
#468=AXIS2_PLACEMENT_3D('',#465,#466,#467);
#469=TOROIDAL_SURFACE('',#468,30.5354084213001,24.);
#470=CARTESIAN_POINT('',(-9.98945607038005,33.508120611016,5.50000000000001));
#471=CARTESIAN_POINT('',(-9.93830665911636,33.1482112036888,5.50000000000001));
#472=CARTESIAN_POINT('',(-9.89515712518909,32.7872114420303,5.50000000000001));
#473=CARTESIAN_POINT('',(-9.82487450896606,32.0636701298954,5.50000000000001));
#474=CARTESIAN_POINT('',(-9.79774079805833,31.7011286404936,5.50000000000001));
#475=CARTESIAN_POINT('',(-9.7403995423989,30.6124145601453,5.50000000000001));
#476=CARTESIAN_POINT('',(-9.73420856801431,29.8848467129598,5.50000000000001));
#477=CARTESIAN_POINT('',(-9.78549820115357,28.4339282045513,5.50000000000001));
#478=CARTESIAN_POINT('',(-9.84280858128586,27.7105714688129,5.50000000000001));
#479=CARTESIAN_POINT('',(-9.97553994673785,26.6315156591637,5.50000000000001));
#480=CARTESIAN_POINT('',(-10.0275821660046,26.2728074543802,5.50000000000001));
#481=CARTESIAN_POINT('',(-10.147096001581,25.5578828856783,5.50000000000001));
#482=CARTESIAN_POINT('',(-10.2145712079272,25.2016671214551,5.50000000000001));
#483=CARTESIAN_POINT('',(-10.4344425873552,24.1633765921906,5.50000000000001));
#484=CARTESIAN_POINT('',(-10.6075473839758,23.4855843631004,5.50000000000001));
#485=CARTESIAN_POINT('',(-11.0086029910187,22.1464325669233,5.50000000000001));
#486=CARTESIAN_POINT('',(-11.2365550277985,21.4850733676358,5.50000000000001));
#487=CARTESIAN_POINT('',(-11.6178803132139,20.5085308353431,5.50000000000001));
#488=CARTESIAN_POINT('',(-11.7515815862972,20.185544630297,5.50000000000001));
#489=CARTESIAN_POINT('',(-12.0317743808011,19.5452661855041,5.50000000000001));
#490=CARTESIAN_POINT('',(-12.1782626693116,19.2279725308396,5.50000000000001));
#491=CARTESIAN_POINT('',(-12.6364991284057,18.2851381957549,5.50000000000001));
#492=CARTESIAN_POINT('',(-12.9670313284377,17.6686123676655,5.50000000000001));
#493=CARTESIAN_POINT('',(-13.690329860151,16.4373255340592,5.50000000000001));
#494=CARTESIAN_POINT('',(-14.0851625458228,15.82378270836,5.50000000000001));
#495=CARTESIAN_POINT('',(-14.9223127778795,14.6299848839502,5.50000000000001));
#496=CARTESIAN_POINT('',(-15.3646321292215,14.0497311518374,5.50000000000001));
#497=CARTESIAN_POINT('',(-16.2929163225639,12.9250629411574,5.50000000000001));
#498=CARTESIAN_POINT('',(-16.7788933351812,12.3806585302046,5.50000000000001));
#499=CARTESIAN_POINT('',(-17.7904350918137,11.3298334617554,5.50000000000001));
#500=CARTESIAN_POINT('',(-18.3160036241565,10.8234164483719,5.50000000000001));
#501=CARTESIAN_POINT('',(-19.154167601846,10.0727446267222,5.50000000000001));
#502=CARTESIAN_POINT('',(-19.4543178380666,9.81445346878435,5.50000000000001));
#503=CARTESIAN_POINT('',(-20.0643821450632,9.30983091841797,5.50000000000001));
#504=CARTESIAN_POINT('',(-20.3742940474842,9.06349690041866,5.50000000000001));
#505=CARTESIAN_POINT('',(-21.3181549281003,8.34243859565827,5.50000000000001));
#506=CARTESIAN_POINT('',(-21.9661028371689,7.88577084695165,5.50000000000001));
#507=CARTESIAN_POINT('',(-22.9632121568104,7.23835075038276,5.50000000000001));
#508=CARTESIAN_POINT('',(-23.3002227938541,7.02856581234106,5.50000000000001));
#509=CARTESIAN_POINT('',(-23.9820820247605,6.62216270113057,5.50000000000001));
#510=CARTESIAN_POINT('',(-24.3269297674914,6.4255431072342,5.50000000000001));
#511=CARTESIAN_POINT('',(-25.0240231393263,6.04618877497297,5.50000000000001));
#512=CARTESIAN_POINT('',(-25.376266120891,5.86344917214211,5.50000000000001));
#513=CARTESIAN_POINT('',(-26.0880232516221,5.51280459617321,5.50000000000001));
#514=CARTESIAN_POINT('',(-26.4475365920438,5.34489798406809,5.50000000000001));
#515=CARTESIAN_POINT('',(-27.2296065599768,5.00083955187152,5.50000000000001));
#516=CARTESIAN_POINT('',(-27.6533592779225,4.82738759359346,5.50000000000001));
#517=CARTESIAN_POINT('',(-28.5104162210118,4.50575744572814,5.50000000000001));
#518=CARTESIAN_POINT('',(-28.9437200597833,4.35757823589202,5.50000000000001));
#519=CARTESIAN_POINT('',(-29.8167010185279,4.0926593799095,5.50000000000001));
#520=CARTESIAN_POINT('',(-30.2563140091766,3.97571098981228,5.50000000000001));
#521=CARTESIAN_POINT('',(-31.1439193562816,3.77877092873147,5.50000000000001));
#522=CARTESIAN_POINT('',(-31.5919098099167,3.698770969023,5.50000000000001));
#523=CARTESIAN_POINT('',(-32.2720873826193,3.61115667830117,5.50000000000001));
#524=CARTESIAN_POINT('',(-32.502239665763,3.58728726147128,5.50000000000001));
#525=CARTESIAN_POINT('',(-32.9634935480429,3.55155115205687,5.50000000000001));
#526=CARTESIAN_POINT('',(-33.1945951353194,3.53968430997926,5.50000000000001));
#527=CARTESIAN_POINT('',(-33.657057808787,3.52832833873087,5.50000000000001));
#528=CARTESIAN_POINT('',(-33.8884188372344,3.52883685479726,5.50000000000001));
#529=CARTESIAN_POINT('',(-34.3507822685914,3.54220662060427,5.50000000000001));
#530=CARTESIAN_POINT('',(-34.5817846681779,3.55506798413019,5.50000000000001));
#531=CARTESIAN_POINT('',(-35.0438108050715,3.59283577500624,5.50000000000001));
#532=CARTESIAN_POINT('',(-35.2748302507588,3.61779443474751,5.50000000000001));
#533=CARTESIAN_POINT('',(-35.7353696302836,3.67907740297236,5.50000000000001));
#534=CARTESIAN_POINT('',(-35.964889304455,3.71540362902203,5.50000000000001));
#535=CARTESIAN_POINT('',(-36.6507574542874,3.84014093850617,5.50000000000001));
#536=CARTESIAN_POINT('',(-37.1043020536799,3.94430064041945,5.50000000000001));
#537=CARTESIAN_POINT('',(-37.8707301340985,4.15152566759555,5.50000000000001));
#538=CARTESIAN_POINT('',(-38.1860218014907,4.24603244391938,5.50000000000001));
#539=CARTESIAN_POINT('',(-38.8117937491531,4.44997362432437,5.50000000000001));
#540=CARTESIAN_POINT('',(-39.1222733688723,4.55941005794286,5.50000000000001));
#541=CARTESIAN_POINT('',(-39.7383870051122,4.79137990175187,5.50000000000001));
#542=CARTESIAN_POINT('',(-40.0440193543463,4.91391771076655,5.50000000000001));
#543=CARTESIAN_POINT('',(-40.6503147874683,5.1706589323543,5.50000000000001));
#544=CARTESIAN_POINT('',(-40.9509780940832,5.3048618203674,5.50000000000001));
#545=CARTESIAN_POINT('',(-41.5481299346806,5.58430136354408,5.50000000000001));
#546=CARTESIAN_POINT('',(-41.8446047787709,5.72956723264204,5.50000000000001));
#547=CARTESIAN_POINT('',(-42.432457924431,6.03008635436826,5.50000000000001));
#548=CARTESIAN_POINT('',(-42.7238358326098,6.18534037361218,5.50000000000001));
#549=CARTESIAN_POINT('',(-43.5899217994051,6.66516317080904,5.50000000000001));
#550=CARTESIAN_POINT('',(-44.1568409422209,7.00391473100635,5.50000000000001));
#551=CARTESIAN_POINT('',(-45.3197558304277,7.7498263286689,5.50000000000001));
#552=CARTESIAN_POINT('',(-45.91354673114,8.16041889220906,5.50000000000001));
#553=CARTESIAN_POINT('',(-47.0710896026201,9.02207526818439,5.50000000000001));
#554=CARTESIAN_POINT('',(-47.6348397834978,9.47314148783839,5.50000000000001));
#555=CARTESIAN_POINT('',(-48.7273818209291,10.4133503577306,5.50000000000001));
#556=CARTESIAN_POINT('',(-49.2562528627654,10.9024008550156,5.50000000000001));
#557=CARTESIAN_POINT('',(-50.2766653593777,11.9181027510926,5.50000000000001));
#558=CARTESIAN_POINT('',(-50.7682041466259,12.4447568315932,5.50000000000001));
#559=CARTESIAN_POINT('',(-51.7945248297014,13.6315520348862,5.50000000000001));
#560=CARTESIAN_POINT('',(-52.3212497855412,14.2986928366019,5.50000000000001));
#561=CARTESIAN_POINT('',(-53.3111149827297,15.6789559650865,5.50000000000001));
#562=CARTESIAN_POINT('',(-53.774245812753,16.3920850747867,5.50000000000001));
#563=CARTESIAN_POINT('',(-54.4169372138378,17.4925554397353,5.50000000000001));
#564=CARTESIAN_POINT('',(-54.6226512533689,17.8648343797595,5.50000000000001));
#565=CARTESIAN_POINT('',(-55.0159713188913,18.6188416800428,5.50000000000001));
#566=CARTESIAN_POINT('',(-55.2035787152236,19.0005693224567,5.50000000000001));
#567=CARTESIAN_POINT('',(-55.5599954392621,19.7725757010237,5.50000000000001));
#568=CARTESIAN_POINT('',(-55.7288099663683,20.1628520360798,5.50000000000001));
#569=CARTESIAN_POINT('',(-56.0471624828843,20.9513001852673,5.50000000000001));
#570=CARTESIAN_POINT('',(-56.1966946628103,21.3494743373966,5.50000000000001));
#571=CARTESIAN_POINT('',(-56.5860650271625,22.4697320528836,5.50000000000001));
#572=CARTESIAN_POINT('',(-56.8040789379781,23.1995318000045,5.50000000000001));
#573=CARTESIAN_POINT('',(-57.1738301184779,24.6757048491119,5.50000000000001));
#574=CARTESIAN_POINT('',(-57.3255738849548,25.4220765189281,5.50000000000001));
#575=CARTESIAN_POINT('',(-57.501912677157,26.5486848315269,5.50000000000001));
#576=CARTESIAN_POINT('',(-57.5521246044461,26.9250644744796,5.50000000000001));
#577=CARTESIAN_POINT('',(-57.6353873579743,27.6796512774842,5.50000000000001));
#578=CARTESIAN_POINT('',(-57.66844238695,28.0578579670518,5.50000000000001));
#579=CARTESIAN_POINT('',(-57.7172452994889,28.8152147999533,5.50000000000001));
#580=CARTESIAN_POINT('',(-57.7330008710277,29.1943644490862,5.50000000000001));
#581=CARTESIAN_POINT('',(-57.7471327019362,29.9529739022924,5.50000000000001));
#582=CARTESIAN_POINT('',(-57.7455091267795,30.3324337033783,5.50000000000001));
#583=CARTESIAN_POINT('',(-57.7223906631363,31.1798160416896,5.50000000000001));
#584=CARTESIAN_POINT('',(-57.6963274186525,31.647626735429,5.50000000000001));
#585=CARTESIAN_POINT('',(-57.6373166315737,32.3472349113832,5.50000000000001));
#586=CARTESIAN_POINT('',(-57.6143508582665,32.5799186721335,5.50000000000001));
#587=CARTESIAN_POINT('',(-57.5617911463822,33.0445936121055,5.50000000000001));
#588=CARTESIAN_POINT('',(-57.5321955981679,33.2765846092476,5.50000000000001));
#589=CARTESIAN_POINT('',(-57.4992911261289,33.508120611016,5.50000000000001));
#590=B_SPLINE_CURVE_WITH_KNOTS('',3,(#470,#471,#472,#473,#474,#475,#476,#477,#478,#479,#480,
#481,#482,#483,#484,#485,#486,#487,#488,#489,#490,#491,#492,#493,#494,#495,#496,#497,#498,#499,
#500,#501,#502,#503,#504,#505,#506,#507,#508,#509,#510,#511,#512,#513,#514,#515,#516,#517,#518,
#519,#520,#521,#522,#523,#524,#525,#526,#527,#528,#529,#530,#531,#532,#533,#534,#535,#536,#537,
#538,#539,#540,#541,#542,#543,#544,#545,#546,#547,#548,#549,#550,#551,#552,#553,#554,#555,#556,
#557,#558,#559,#560,#561,#562,#563,#564,#565,#566,#567,#568,#569,#570,#571,#572,#573,#574,#575,
#576,#577,#578,#579,#580,#581,#582,#583,#584,#585,#586,#587,#588,#589),.UNSPECIFIED.,.F.,.F.,(4,
2,2,2,2,2,2,2,2,2,2,2,2,2,2,2,2,2,2,2,2,2,2,2,2,2,2,2,2,2,2,2,2,2,2,2,2,2,2,2,2,2,2,2,2,2,2,2,2,
2,2,2,2,2,2,2,2,2,2,4),(0.,1.09039714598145,2.18075149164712,4.36053739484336,6.53449407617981,
7.62159151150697,8.70894208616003,10.8050697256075,12.9012442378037,13.9496956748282,
14.9978827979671,17.0941549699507,19.2806561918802,21.467240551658,23.6544363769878,
25.8418417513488,27.0295255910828,28.2169474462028,30.5922977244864,31.7829934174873,
32.9735604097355,34.1637082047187,35.3537243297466,36.7266617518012,38.0995437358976,
39.4630057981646,40.826161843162,41.5200551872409,42.2139398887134,42.9076925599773,
43.6014516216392,44.2982331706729,44.9951323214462,46.3892696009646,47.3763880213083,
48.3636407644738,49.351226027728,50.3387669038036,51.3290125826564,52.3193343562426,
54.2991210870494,56.463175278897,58.6273582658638,60.7864456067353,62.9456870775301,
65.4922136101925,68.0391165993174,69.3147152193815,70.5902172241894,71.8653654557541,
73.1408969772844,75.4227246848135,77.7043286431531,78.8431442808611,79.9816808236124,
81.1197111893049,82.2577307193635,83.6624856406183,84.3638485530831,85.0653819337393),.UNSPECIFIED.);
#591=CARTESIAN_POINT('',(-42.,5.80947501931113,5.50000000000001));
#592=VERTEX_POINT('',#591);
#593=EDGE_CURVE('E325',#456,#592,#590,.T.);
#594=ORIENTED_EDGE('',*,*,#593,.F.);
#595=ORIENTED_EDGE('',*,*,#457,.F.);
#596=CARTESIAN_POINT('',(-57.4992911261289,-33.508120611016,5.50000000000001));
#597=CARTESIAN_POINT('',(-57.5504405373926,-33.1482112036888,5.50000000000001));
#598=CARTESIAN_POINT('',(-57.5935900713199,-32.7872114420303,5.50000000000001));
#599=CARTESIAN_POINT('',(-57.6638726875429,-32.0636701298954,5.50000000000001));
#600=CARTESIAN_POINT('',(-57.6910063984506,-31.7011286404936,5.50000000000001));
#601=CARTESIAN_POINT('',(-57.7483476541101,-30.6124145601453,5.50000000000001));
#602=CARTESIAN_POINT('',(-57.7545386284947,-29.8848467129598,5.50000000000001));
#603=CARTESIAN_POINT('',(-57.7032489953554,-28.4339282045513,5.50000000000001));
#604=CARTESIAN_POINT('',(-57.6459386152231,-27.7105714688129,5.50000000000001));
#605=CARTESIAN_POINT('',(-57.5132072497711,-26.6315156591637,5.50000000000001));
#606=CARTESIAN_POINT('',(-57.4611650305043,-26.2728074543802,5.50000000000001));
#607=CARTESIAN_POINT('',(-57.3416511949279,-25.5578828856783,5.50000000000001));
#608=CARTESIAN_POINT('',(-57.2741759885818,-25.2016671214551,5.50000000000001));
#609=CARTESIAN_POINT('',(-57.0543046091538,-24.1633765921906,5.50000000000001));
#610=CARTESIAN_POINT('',(-56.8811998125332,-23.4855843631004,5.50000000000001));
#611=CARTESIAN_POINT('',(-56.4801442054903,-22.1464325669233,5.50000000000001));
#612=CARTESIAN_POINT('',(-56.2521921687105,-21.4850733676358,5.50000000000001));
#613=CARTESIAN_POINT('',(-55.8708668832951,-20.5085308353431,5.50000000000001));
#614=CARTESIAN_POINT('',(-55.7371656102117,-20.185544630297,5.50000000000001));
#615=CARTESIAN_POINT('',(-55.4569728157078,-19.5452661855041,5.50000000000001));
#616=CARTESIAN_POINT('',(-55.3104845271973,-19.2279725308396,5.50000000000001));
#617=CARTESIAN_POINT('',(-54.8522480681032,-18.2851381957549,5.50000000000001));
#618=CARTESIAN_POINT('',(-54.5217158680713,-17.6686123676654,5.50000000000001));
#619=CARTESIAN_POINT('',(-53.7984173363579,-16.4373255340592,5.50000000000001));
#620=CARTESIAN_POINT('',(-53.4035846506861,-15.82378270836,5.50000000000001));
#621=CARTESIAN_POINT('',(-52.5664344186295,-14.6299848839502,5.50000000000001));
#622=CARTESIAN_POINT('',(-52.1241150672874,-14.0497311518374,5.50000000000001));
#623=CARTESIAN_POINT('',(-51.195830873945,-12.9250629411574,5.50000000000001));
#624=CARTESIAN_POINT('',(-50.7098538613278,-12.3806585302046,5.50000000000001));
#625=CARTESIAN_POINT('',(-49.6983121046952,-11.3298334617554,5.50000000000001));
#626=CARTESIAN_POINT('',(-49.1727435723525,-10.8234164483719,5.50000000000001));
#627=CARTESIAN_POINT('',(-48.334579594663,-10.0727446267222,5.50000000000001));
#628=CARTESIAN_POINT('',(-48.0344293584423,-9.81445346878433,5.50000000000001));
#629=CARTESIAN_POINT('',(-47.4243650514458,-9.30983091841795,5.50000000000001));
#630=CARTESIAN_POINT('',(-47.1144531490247,-9.06349690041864,5.50000000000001));
#631=CARTESIAN_POINT('',(-46.1705922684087,-8.34243859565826,5.50000000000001));
#632=CARTESIAN_POINT('',(-45.5226443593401,-7.88577084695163,5.50000000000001));
#633=CARTESIAN_POINT('',(-44.5255350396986,-7.23835075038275,5.50000000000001));
#634=CARTESIAN_POINT('',(-44.1885244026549,-7.02856581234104,5.50000000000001));
#635=CARTESIAN_POINT('',(-43.5066651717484,-6.62216270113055,5.50000000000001));
#636=CARTESIAN_POINT('',(-43.1618174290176,-6.42554310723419,5.50000000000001));
#637=CARTESIAN_POINT('',(-42.4647240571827,-6.04618877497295,5.50000000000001));
#638=CARTESIAN_POINT('',(-42.1124810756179,-5.86344917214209,5.50000000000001));
#639=CARTESIAN_POINT('',(-41.4007239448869,-5.51280459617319,5.50000000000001));
#640=CARTESIAN_POINT('',(-41.0412106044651,-5.34489798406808,5.50000000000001));
#641=CARTESIAN_POINT('',(-40.2591406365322,-5.00083955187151,5.50000000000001));
#642=CARTESIAN_POINT('',(-39.8353879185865,-4.82738759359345,5.50000000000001));
#643=CARTESIAN_POINT('',(-38.9783309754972,-4.50575744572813,5.50000000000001));
#644=CARTESIAN_POINT('',(-38.5450271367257,-4.35757823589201,5.50000000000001));
#645=CARTESIAN_POINT('',(-37.6720461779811,-4.09265937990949,5.50000000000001));
#646=CARTESIAN_POINT('',(-37.2324331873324,-3.97571098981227,5.50000000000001));
#647=CARTESIAN_POINT('',(-36.3448278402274,-3.77877092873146,5.50000000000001));
#648=CARTESIAN_POINT('',(-35.8968373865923,-3.69877096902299,5.50000000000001));
#649=CARTESIAN_POINT('',(-35.2166598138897,-3.61115667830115,5.50000000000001));
#650=CARTESIAN_POINT('',(-34.986507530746,-3.58728726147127,5.50000000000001));
#651=CARTESIAN_POINT('',(-34.5252536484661,-3.55155115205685,5.50000000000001));
#652=CARTESIAN_POINT('',(-34.2941520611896,-3.53968430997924,5.50000000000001));
#653=CARTESIAN_POINT('',(-33.8316893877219,-3.52832833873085,5.50000000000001));
#654=CARTESIAN_POINT('',(-33.6003283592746,-3.52883685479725,5.50000000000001));
#655=CARTESIAN_POINT('',(-33.1379649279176,-3.54220662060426,5.50000000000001));
#656=CARTESIAN_POINT('',(-32.9069625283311,-3.55506798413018,5.50000000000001));
#657=CARTESIAN_POINT('',(-32.4449363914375,-3.59283577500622,5.50000000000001));
#658=CARTESIAN_POINT('',(-32.2139169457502,-3.6177944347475,5.50000000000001));
#659=CARTESIAN_POINT('',(-31.7533775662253,-3.67907740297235,5.50000000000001));
#660=CARTESIAN_POINT('',(-31.523857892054,-3.71540362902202,5.50000000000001));
#661=CARTESIAN_POINT('',(-30.8379897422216,-3.84014093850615,5.50000000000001));
#662=CARTESIAN_POINT('',(-30.3844451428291,-3.94430064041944,5.50000000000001));
#663=CARTESIAN_POINT('',(-29.6180170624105,-4.15152566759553,5.50000000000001));
#664=CARTESIAN_POINT('',(-29.3027253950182,-4.24603244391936,5.50000000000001));
#665=CARTESIAN_POINT('',(-28.6769534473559,-4.44997362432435,5.50000000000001));
#666=CARTESIAN_POINT('',(-28.3664738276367,-4.55941005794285,5.50000000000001));
#667=CARTESIAN_POINT('',(-27.7503601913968,-4.79137990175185,5.50000000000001));
#668=CARTESIAN_POINT('',(-27.4447278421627,-4.91391771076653,5.50000000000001));
#669=CARTESIAN_POINT('',(-26.8384324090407,-5.17065893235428,5.50000000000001));
#670=CARTESIAN_POINT('',(-26.5377691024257,-5.30486182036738,5.50000000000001));
#671=CARTESIAN_POINT('',(-25.9406172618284,-5.58430136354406,5.50000000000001));
#672=CARTESIAN_POINT('',(-25.6441424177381,-5.72956723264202,5.50000000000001));
#673=CARTESIAN_POINT('',(-25.056289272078,-6.03008635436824,5.50000000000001));
#674=CARTESIAN_POINT('',(-24.7649113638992,-6.18534037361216,5.50000000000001));
#675=CARTESIAN_POINT('',(-23.8988253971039,-6.66516317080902,5.50000000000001));
#676=CARTESIAN_POINT('',(-23.3319062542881,-7.00391473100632,5.50000000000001));
#677=CARTESIAN_POINT('',(-22.1689913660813,-7.74982632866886,5.50000000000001));
#678=CARTESIAN_POINT('',(-21.5752004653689,-8.16041889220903,5.50000000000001));
#679=CARTESIAN_POINT('',(-20.4176575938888,-9.02207526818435,5.50000000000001));
#680=CARTESIAN_POINT('',(-19.8539074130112,-9.47314148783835,5.50000000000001));
#681=CARTESIAN_POINT('',(-18.7613653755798,-10.4133503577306,5.50000000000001));
#682=CARTESIAN_POINT('',(-18.2324943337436,-10.9024008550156,5.50000000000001));
#683=CARTESIAN_POINT('',(-17.2120818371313,-11.9181027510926,5.50000000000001));
#684=CARTESIAN_POINT('',(-16.7205430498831,-12.4447568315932,5.50000000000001));
#685=CARTESIAN_POINT('',(-15.6942223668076,-13.6315520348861,5.50000000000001));
#686=CARTESIAN_POINT('',(-15.1674974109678,-14.2986928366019,5.50000000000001));
#687=CARTESIAN_POINT('',(-14.1776322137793,-15.6789559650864,5.50000000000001));
#688=CARTESIAN_POINT('',(-13.714501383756,-16.3920850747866,5.50000000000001));
#689=CARTESIAN_POINT('',(-13.0718099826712,-17.4925554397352,5.50000000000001));
#690=CARTESIAN_POINT('',(-12.8660959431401,-17.8648343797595,5.50000000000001));
#691=CARTESIAN_POINT('',(-12.4727758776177,-18.6188416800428,5.50000000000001));
#692=CARTESIAN_POINT('',(-12.2851684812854,-19.0005693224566,5.50000000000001));
#693=CARTESIAN_POINT('',(-11.9287517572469,-19.7725757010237,5.50000000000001));
#694=CARTESIAN_POINT('',(-11.7599372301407,-20.1628520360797,5.50000000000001));
#695=CARTESIAN_POINT('',(-11.4415847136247,-20.9513001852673,5.50000000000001));
#696=CARTESIAN_POINT('',(-11.2920525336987,-21.3494743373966,5.50000000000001));
#697=CARTESIAN_POINT('',(-10.9026821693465,-22.4697320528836,5.50000000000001));
#698=CARTESIAN_POINT('',(-10.6846682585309,-23.1995318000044,5.50000000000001));
#699=CARTESIAN_POINT('',(-10.314917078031,-24.6757048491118,5.50000000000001));
#700=CARTESIAN_POINT('',(-10.1631733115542,-25.4220765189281,5.50000000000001));
#701=CARTESIAN_POINT('',(-9.98683451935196,-26.5486848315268,5.50000000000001));
#702=CARTESIAN_POINT('',(-9.93662259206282,-26.9250644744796,5.50000000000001));
#703=CARTESIAN_POINT('',(-9.85335983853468,-27.6796512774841,5.50000000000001));
#704=CARTESIAN_POINT('',(-9.82030480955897,-28.0578579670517,5.50000000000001));
#705=CARTESIAN_POINT('',(-9.77150189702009,-28.8152147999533,5.50000000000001));
#706=CARTESIAN_POINT('',(-9.75574632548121,-29.1943644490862,5.50000000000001));
#707=CARTESIAN_POINT('',(-9.7416144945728,-29.9529739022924,5.50000000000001));
#708=CARTESIAN_POINT('',(-9.74323806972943,-30.3324337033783,5.50000000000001));
#709=CARTESIAN_POINT('',(-9.76635653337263,-31.1798160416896,5.50000000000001));
#710=CARTESIAN_POINT('',(-9.79241977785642,-31.6476267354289,5.50000000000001));
#711=CARTESIAN_POINT('',(-9.85143056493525,-32.3472349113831,5.50000000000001));
#712=CARTESIAN_POINT('',(-9.8743963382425,-32.5799186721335,5.50000000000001));
#713=CARTESIAN_POINT('',(-9.9269560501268,-33.0445936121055,5.50000000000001));
#714=CARTESIAN_POINT('',(-9.95655159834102,-33.2765846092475,5.50000000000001));
#715=CARTESIAN_POINT('',(-9.98945607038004,-33.508120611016,5.50000000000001));
#716=B_SPLINE_CURVE_WITH_KNOTS('',3,(#596,#597,#598,#599,#600,#601,#602,#603,#604,#605,#606,
#607,#608,#609,#610,#611,#612,#613,#614,#615,#616,#617,#618,#619,#620,#621,#622,#623,#624,#625,
#626,#627,#628,#629,#630,#631,#632,#633,#634,#635,#636,#637,#638,#639,#640,#641,#642,#643,#644,
#645,#646,#647,#648,#649,#650,#651,#652,#653,#654,#655,#656,#657,#658,#659,#660,#661,#662,#663,
#664,#665,#666,#667,#668,#669,#670,#671,#672,#673,#674,#675,#676,#677,#678,#679,#680,#681,#682,
#683,#684,#685,#686,#687,#688,#689,#690,#691,#692,#693,#694,#695,#696,#697,#698,#699,#700,#701,
#702,#703,#704,#705,#706,#707,#708,#709,#710,#711,#712,#713,#714,#715),.UNSPECIFIED.,.F.,.F.,(4,
2,2,2,2,2,2,2,2,2,2,2,2,2,2,2,2,2,2,2,2,2,2,2,2,2,2,2,2,2,2,2,2,2,2,2,2,2,2,2,2,2,2,2,2,2,2,2,2,
2,2,2,2,2,2,2,2,2,2,4),(0.,1.09039714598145,2.18075149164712,4.36053739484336,6.53449407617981,
7.62159151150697,8.70894208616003,10.8050697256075,12.9012442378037,13.9496956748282,
14.9978827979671,17.0941549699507,19.2806561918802,21.467240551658,23.6544363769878,
25.8418417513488,27.0295255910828,28.2169474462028,30.5922977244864,31.7829934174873,
32.9735604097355,34.1637082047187,35.3537243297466,36.7266617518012,38.0995437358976,
39.4630057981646,40.826161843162,41.5200551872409,42.2139398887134,42.9076925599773,
43.6014516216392,44.2982331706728,44.9951323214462,46.3892696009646,47.3763880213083,
48.3636407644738,49.351226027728,50.3387669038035,51.3290125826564,52.3193343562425,
54.2991210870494,56.4631752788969,58.6273582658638,60.7864456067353,62.94568707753,
65.4922136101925,68.0391165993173,69.3147152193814,70.5902172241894,71.865365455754,
73.1408969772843,75.4227246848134,77.7043286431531,78.843144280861,79.9816808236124,
81.1197111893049,82.2577307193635,83.6624856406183,84.3638485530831,85.0653819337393),.UNSPECIFIED.);
#717=CARTESIAN_POINT('',(-42.,-5.80947501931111,5.50000000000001));
#718=VERTEX_POINT('',#717);
#719=EDGE_CURVE('E310',#718,#447,#716,.T.);
#720=ORIENTED_EDGE('',*,*,#719,.F.);
#721=CARTESIAN_POINT('',(-42.,0.,0.));
#722=DIRECTION('',(1.,0.,0.));
#723=DIRECTION('',(0.,1.,0.));
#724=AXIS2_PLACEMENT_3D('',#721,#722,#723);
#725=CIRCLE('',#724,8.);
#726=EDGE_CURVE('E360',#718,#592,#725,.T.);
#727=ORIENTED_EDGE('',*,*,#726,.T.);
#728=EDGE_LOOP('',(#594,#595,#720,#727));
#729=FACE_BOUND('',#728,.T.);
#730=ADVANCED_FACE('F297',(#729),#469,.F.);
#731=CARTESIAN_POINT('',(-100.,0.,0.));
#732=DIRECTION('',(1.,0.,0.));
#733=DIRECTION('',(0.,1.,0.));
#734=AXIS2_PLACEMENT_3D('',#731,#732,#733);
#735=CYLINDRICAL_SURFACE('',#734,8.);
#736=DIRECTION('',(1.,0.,0.));
#737=VECTOR('',#736,1.);
#738=CARTESIAN_POINT('',(-100.,5.80947501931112,5.50000000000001));
#739=LINE('',#738,#737);
#740=CARTESIAN_POINT('',(-49.,5.80947501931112,5.50000000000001));
#741=VERTEX_POINT('',#740);
#742=EDGE_CURVE('E331',#592,#741,#739,.F.);
#743=ORIENTED_EDGE('',*,*,#742,.F.);
#744=ORIENTED_EDGE('',*,*,#726,.F.);
#745=DIRECTION('',(1.,0.,0.));
#746=VECTOR('',#745,1.);
#747=CARTESIAN_POINT('',(-100.,-5.80947501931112,5.50000000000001));
#748=LINE('',#747,#746);
#749=CARTESIAN_POINT('',(-49.,-5.80947501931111,5.50000000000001));
#750=VERTEX_POINT('',#749);
#751=EDGE_CURVE('E589',#750,#718,#748,.T.);
#752=ORIENTED_EDGE('',*,*,#751,.F.);
#753=CARTESIAN_POINT('',(-49.,0.,0.));
#754=DIRECTION('',(1.,0.,0.));
#755=DIRECTION('',(0.,1.,0.));
#756=AXIS2_PLACEMENT_3D('',#753,#754,#755);
#757=CIRCLE('',#756,7.99999999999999);
#758=EDGE_CURVE('E357',#750,#741,#757,.T.);
#759=ORIENTED_EDGE('',*,*,#758,.T.);
#760=EDGE_LOOP('',(#743,#744,#752,#759));
#761=FACE_BOUND('',#760,.T.);
#762=ADVANCED_FACE('F539',(#761),#735,.T.);
#763=CARTESIAN_POINT('',(-49.,8.,0.));
#764=DIRECTION('',(-1.,0.,0.));
#765=DIRECTION('',(0.,-1.,0.));
#766=AXIS2_PLACEMENT_3D('',#763,#764,#765);
#767=PLANE('',#766);
#768=DIRECTION('',(0.,-1.,0.));
#769=VECTOR('',#768,1.);
#770=CARTESIAN_POINT('',(-49.,8.,5.50000000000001));
#771=LINE('',#770,#769);
#772=CARTESIAN_POINT('',(-49.,4.33012701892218,5.50000000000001));
#773=VERTEX_POINT('',#772);
#774=EDGE_CURVE('E333',#741,#773,#771,.T.);
#775=ORIENTED_EDGE('',*,*,#774,.F.);
#776=ORIENTED_EDGE('',*,*,#758,.F.);
#777=CARTESIAN_POINT('',(-49.,-4.33012701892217,5.50000000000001));
#778=VERTEX_POINT('',#777);
#779=EDGE_CURVE('E586',#778,#750,#771,.T.);
#780=ORIENTED_EDGE('',*,*,#779,.F.);
#781=CARTESIAN_POINT('',(-49.,0.,0.));
#782=DIRECTION('',(1.,0.,0.));
#783=DIRECTION('',(0.,1.,0.));
#784=AXIS2_PLACEMENT_3D('',#781,#782,#783);
#785=CIRCLE('',#784,7.);
#786=EDGE_CURVE('E354',#778,#773,#785,.T.);
#787=ORIENTED_EDGE('',*,*,#786,.T.);
#788=EDGE_LOOP('',(#775,#776,#780,#787));
#789=FACE_BOUND('',#788,.T.);
#790=ADVANCED_FACE('F406',(#789),#767,.T.);
#791=CARTESIAN_POINT('',(-100.,0.,0.));
#792=DIRECTION('',(1.,0.,0.));
#793=DIRECTION('',(0.,1.,0.));
#794=AXIS2_PLACEMENT_3D('',#791,#792,#793);
#795=CYLINDRICAL_SURFACE('',#794,7.);
#796=DIRECTION('',(1.,0.,0.));
#797=VECTOR('',#796,1.);
#798=CARTESIAN_POINT('',(-100.,4.33012701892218,5.50000000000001));
#799=LINE('',#798,#797);
#800=CARTESIAN_POINT('',(-50.,4.33012701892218,5.50000000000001));
#801=VERTEX_POINT('',#800);
#802=EDGE_CURVE('E334',#773,#801,#799,.F.);
#803=ORIENTED_EDGE('',*,*,#802,.F.);
#804=ORIENTED_EDGE('',*,*,#786,.F.);
#805=DIRECTION('',(1.,0.,0.));
#806=VECTOR('',#805,1.);
#807=CARTESIAN_POINT('',(-100.,-4.33012701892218,5.50000000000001));
#808=LINE('',#807,#806);
#809=CARTESIAN_POINT('',(-50.,-4.33012701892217,5.50000000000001));
#810=VERTEX_POINT('',#809);
#811=EDGE_CURVE('E585',#810,#778,#808,.T.);
#812=ORIENTED_EDGE('',*,*,#811,.F.);
#813=CARTESIAN_POINT('',(-50.,0.,0.));
#814=DIRECTION('',(1.,0.,0.));
#815=DIRECTION('',(0.,1.,0.));
#816=AXIS2_PLACEMENT_3D('',#813,#814,#815);
#817=CIRCLE('',#816,6.99999999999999);
#818=EDGE_CURVE('E351',#810,#801,#817,.T.);
#819=ORIENTED_EDGE('',*,*,#818,.T.);
#820=EDGE_LOOP('',(#803,#804,#812,#819));
#821=FACE_BOUND('',#820,.T.);
#822=ADVANCED_FACE('F401',(#821),#795,.T.);
#823=CARTESIAN_POINT('',(-50.,7.,0.));
#824=DIRECTION('',(-1.,0.,0.));
#825=DIRECTION('',(0.,-1.,0.));
#826=AXIS2_PLACEMENT_3D('',#823,#824,#825);
#827=PLANE('',#826);
#828=DIRECTION('',(0.,-1.,0.));
#829=VECTOR('',#828,1.);
#830=CARTESIAN_POINT('',(-50.,7.,5.50000000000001));
#831=LINE('',#830,#829);
#832=EDGE_CURVE('E370',#801,#810,#831,.T.);
#833=ORIENTED_EDGE('',*,*,#832,.F.);
#834=ORIENTED_EDGE('',*,*,#818,.F.);
#835=EDGE_LOOP('',(#833,#834));
#836=FACE_BOUND('',#835,.T.);
#837=CARTESIAN_POINT('',(-50.,0.,0.));
#838=DIRECTION('',(1.,0.,0.));
#839=DIRECTION('',(0.,1.,0.));
#840=AXIS2_PLACEMENT_3D('',#837,#838,#839);
#841=CIRCLE('',#840,2.);
#842=CARTESIAN_POINT('',(-50.,2.00000000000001,0.));
#843=VERTEX_POINT('',#842);
#844=EDGE_CURVE('E348',#843,#843,#841,.T.);
#845=ORIENTED_EDGE('',*,*,#844,.T.);
#846=EDGE_LOOP('',(#845));
#847=FACE_BOUND('',#846,.T.);
#848=ADVANCED_FACE('F397',(#836,#847),#827,.T.);
#849=CARTESIAN_POINT('',(-100.,0.,0.));
#850=DIRECTION('',(1.,0.,0.));
#851=DIRECTION('',(0.,1.,0.));
#852=AXIS2_PLACEMENT_3D('',#849,#850,#851);
#853=CYLINDRICAL_SURFACE('',#852,2.);
#854=CARTESIAN_POINT('',(-119.081136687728,0.,0.));
#855=DIRECTION('',(0.0523359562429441,0.,0.998629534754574));
#856=DIRECTION('',(0.998629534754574,0.,-0.0523359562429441));
#857=AXIS2_PLACEMENT_3D('',#854,#855,#856);
#858=ELLIPSE('',#857,38.2146452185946,2.);
#859=CARTESIAN_POINT('',(-86.,0.997122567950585,-1.73370890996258));
#860=VERTEX_POINT('',#859);
#861=EDGE_CURVE('E261',#860,#54,#858,.F.);
#862=ORIENTED_EDGE('',*,*,#861,.F.);
#863=CARTESIAN_POINT('',(-86.,0.997122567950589,1.73370890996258));
#864=VERTEX_POINT('',#863);
#865=EDGE_CURVE('E344',#860,#864,#63,.T.);
#866=ORIENTED_EDGE('',*,*,#865,.T.);
#867=CARTESIAN_POINT('',(-119.081136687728,0.,0.));
#868=DIRECTION('',(0.0523359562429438,0.,-0.998629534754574));
#869=DIRECTION('',(0.998629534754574,0.,0.0523359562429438));
#870=AXIS2_PLACEMENT_3D('',#867,#868,#869);
#871=ELLIPSE('',#870,38.2146452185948,2.);
#872=EDGE_CURVE('E236',#65,#864,#871,.F.);
#873=ORIENTED_EDGE('',*,*,#872,.F.);
#874=ORIENTED_EDGE('',*,*,#66,.T.);
#875=EDGE_LOOP('',(#862,#866,#873,#874));
#876=FACE_BOUND('',#875,.T.);
#877=ORIENTED_EDGE('',*,*,#844,.F.);
#878=EDGE_LOOP('',(#877));
#879=FACE_BOUND('',#878,.T.);
#880=ADVANCED_FACE('F246',(#876,#879),#853,.T.);
#881=CARTESIAN_POINT('',(-94.0002,3.24384339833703,-1.31443619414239));
#882=CARTESIAN_POINT('',(-93.7596579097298,3.1900645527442,-1.32704247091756));
#883=CARTESIAN_POINT('',(-93.5192119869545,3.13585064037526,-1.33964370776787));
#884=CARTESIAN_POINT('',(-93.038553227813,3.02637790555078,-1.36483396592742));
#885=CARTESIAN_POINT('',(-92.7983403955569,2.97111906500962,-1.37742298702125));
#886=CARTESIAN_POINT('',(-92.3181143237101,2.8593643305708,-1.40259056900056));
#887=CARTESIAN_POINT('',(-92.0781011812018,2.80286801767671,-1.41516912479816));
#888=CARTESIAN_POINT('',(-91.5984216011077,2.68842317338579,-1.44030806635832));
#889=CARTESIAN_POINT('',(-91.3587551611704,2.63047465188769,-1.45286845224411));
#890=CARTESIAN_POINT('',(-90.8807458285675,2.5130428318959,-1.47791985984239));
#891=CARTESIAN_POINT('',(-90.6424013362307,2.45356607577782,-1.4904109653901));
#892=CARTESIAN_POINT('',(-90.1662557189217,2.33247168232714,-1.51536469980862));
#893=CARTESIAN_POINT('',(-89.9284545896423,2.27085406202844,-1.52782732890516));
#894=CARTESIAN_POINT('',(-89.4535670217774,2.14492489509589,-1.55271513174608));
#895=CARTESIAN_POINT('',(-89.216480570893,2.08061339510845,-1.56514030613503));
#896=CARTESIAN_POINT('',(-88.7432791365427,1.94850747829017,-1.58993974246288));
#897=CARTESIAN_POINT('',(-88.5071641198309,1.88071318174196,-1.60231400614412));
#898=CARTESIAN_POINT('',(-88.0790308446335,1.75314065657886,-1.62475152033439));
#899=CARTESIAN_POINT('',(-87.8867824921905,1.69413893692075,-1.63482682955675));
#900=CARTESIAN_POINT('',(-87.5036598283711,1.57196725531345,-1.65490543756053));
#901=CARTESIAN_POINT('',(-87.3127851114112,1.50879858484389,-1.66490875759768));
#902=CARTESIAN_POINT('',(-87.0278448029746,1.40959258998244,-1.67984184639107));
#903=CARTESIAN_POINT('',(-86.9330171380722,1.37575256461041,-1.6848115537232));
#904=CARTESIAN_POINT('',(-86.7440315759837,1.30626984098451,-1.69471586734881));
#905=CARTESIAN_POINT('',(-86.6498736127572,1.27062732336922,-1.69965047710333));
#906=CARTESIAN_POINT('',(-86.4623264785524,1.19708852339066,-1.7094794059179));
#907=CARTESIAN_POINT('',(-86.3689381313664,1.15919011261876,-1.71437368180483));
#908=CARTESIAN_POINT('',(-86.1833644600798,1.08047106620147,-1.72409918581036));
#909=CARTESIAN_POINT('',(-86.0911795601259,1.03964943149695,-1.72893039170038));
#910=CARTESIAN_POINT('',(-85.9998,0.997029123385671,-1.73371939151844));
#911=B_SPLINE_CURVE_WITH_KNOTS('',3,(#881,#882,#883,#884,#885,#886,#887,#888,#889,#890,#891,
#892,#893,#894,#895,#896,#897,#898,#899,#900,#901,#902,#903,#904,#905,#906,#907,#908,#909,#910),
.UNSPECIFIED.,.F.,.F.,(4,2,2,2,2,2,2,2,2,2,2,2,2,2,4),(0.,0.740408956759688,1.48083074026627,
2.2215072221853,2.96217865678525,3.70008308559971,4.43798164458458,5.17586743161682,
5.91372775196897,6.51774967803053,7.12158526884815,7.42399295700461,7.72637039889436,
8.02903779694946,8.33180913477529),.UNSPECIFIED.);
#912=CARTESIAN_POINT('',(-94.,3.24379868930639,-1.31444667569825));
#913=VERTEX_POINT('',#912);
#914=EDGE_CURVE('E254',#913,#860,#911,.T.);
#915=ORIENTED_EDGE('',*,*,#914,.F.);
#916=CARTESIAN_POINT('',(-94.,3.24379868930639,1.31444667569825));
#917=VERTEX_POINT('',#916);
#918=EDGE_CURVE('E340',#913,#917,#107,.T.);
#919=ORIENTED_EDGE('',*,*,#918,.T.);
#920=CARTESIAN_POINT('',(-85.9998,0.997029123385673,1.73371939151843));
#921=CARTESIAN_POINT('',(-86.0641111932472,1.02705859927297,1.73034898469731));
#922=CARTESIAN_POINT('',(-86.1288400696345,1.05616798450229,1.72695668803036));
#923=CARTESIAN_POINT('',(-86.2589632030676,1.11282617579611,1.72013722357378));
#924=CARTESIAN_POINT('',(-86.3243573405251,1.14037525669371,1.71671006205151));
#925=CARTESIAN_POINT('',(-86.5212414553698,1.2210856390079,1.70639180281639));
#926=CARTESIAN_POINT('',(-86.6535075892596,1.27234401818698,1.69946002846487));
#927=CARTESIAN_POINT('',(-86.9192182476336,1.37111150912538,1.68553472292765));
#928=CARTESIAN_POINT('',(-87.0526610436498,1.41862534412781,1.67854128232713));
#929=CARTESIAN_POINT('',(-87.3205297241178,1.51085295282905,1.66450287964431));
#930=CARTESIAN_POINT('',(-87.454955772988,1.5555662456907,1.65745790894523));
#931=CARTESIAN_POINT('',(-87.7242744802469,1.64269849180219,1.64334351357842));
#932=CARTESIAN_POINT('',(-87.8591658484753,1.68512146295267,1.63627415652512));
#933=CARTESIAN_POINT('',(-88.1294872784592,1.76817316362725,1.62210721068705));
#934=CARTESIAN_POINT('',(-88.2649173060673,1.80880200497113,1.61500962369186));
#935=CARTESIAN_POINT('',(-88.6719647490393,1.92851287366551,1.59367717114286));
#936=CARTESIAN_POINT('',(-88.9442298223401,2.00538437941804,1.57940836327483));
#937=CARTESIAN_POINT('',(-89.6123224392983,2.18849639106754,1.54439511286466));
#938=CARTESIAN_POINT('',(-90.0087736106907,2.2924370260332,1.52361798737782));
#939=CARTESIAN_POINT('',(-90.8030965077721,2.49441785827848,1.48198928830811));
#940=CARTESIAN_POINT('',(-91.2009680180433,2.59245891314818,1.46113772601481));
#941=CARTESIAN_POINT('',(-91.9986411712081,2.78452833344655,1.41933344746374));
#942=CARTESIAN_POINT('',(-92.3984451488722,2.8785469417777,1.39838060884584));
#943=CARTESIAN_POINT('',(-92.998711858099,3.01718603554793,1.36692196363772));
#944=CARTESIAN_POINT('',(-93.1989007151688,3.06300237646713,1.35643051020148));
#945=CARTESIAN_POINT('',(-93.5994368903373,3.15392922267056,1.33543929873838));
#946=CARTESIAN_POINT('',(-93.7997842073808,3.1990397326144,1.32493954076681));
#947=CARTESIAN_POINT('',(-94.0002,3.24384339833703,1.31443619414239));
#948=B_SPLINE_CURVE_WITH_KNOTS('',3,(#920,#921,#922,#923,#924,#925,#926,#927,#928,#929,#930,
#931,#932,#933,#934,#935,#936,#937,#938,#939,#940,#941,#942,#943,#944,#945,#946,#947),
.UNSPECIFIED.,.F.,.F.,(4,2,2,2,2,2,2,2,2,2,2,2,2,4),(0.,0.213148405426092,0.426259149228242,
0.852235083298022,1.27766480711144,1.70316737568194,2.12789746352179,2.55260104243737,
3.40235387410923,4.63341377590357,5.86429429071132,7.09800838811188,7.71490542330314,
8.3317983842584),.UNSPECIFIED.);
#949=EDGE_CURVE('E230',#864,#917,#948,.T.);
#950=ORIENTED_EDGE('',*,*,#949,.F.);
#951=ORIENTED_EDGE('',*,*,#865,.F.);
#952=EDGE_LOOP('',(#915,#919,#950,#951));
#953=FACE_BOUND('',#952,.T.);
#954=ADVANCED_FACE('F242',(#953),#23,.T.);
#955=CARTESIAN_POINT('',(-100.0002,1.73199912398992,-0.999989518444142));
#956=CARTESIAN_POINT('',(-99.7407971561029,1.7990207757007,-1.0135842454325));
#957=CARTESIAN_POINT('',(-99.4813023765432,1.865683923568,-1.02718379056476));
#958=CARTESIAN_POINT('',(-98.9621702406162,1.9984495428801,-1.05439035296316));
#959=CARTESIAN_POINT('',(-98.7025328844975,2.0645520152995,-1.06799737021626));
#960=CARTESIAN_POINT('',(-97.9234699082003,2.26225266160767,-1.10882633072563));
#961=CARTESIAN_POINT('',(-97.4038910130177,2.39324467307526,-1.13605630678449));
#962=CARTESIAN_POINT('',(-96.4036258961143,2.64443239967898,-1.18847798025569));
#963=CARTESIAN_POINT('',(-95.9229572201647,2.76469831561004,-1.21366875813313));
#964=CARTESIAN_POINT('',(-94.961472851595,3.00464833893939,-1.26405801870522));
#965=CARTESIAN_POINT('',(-94.4806571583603,3.12433244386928,-1.28925650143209));
#966=CARTESIAN_POINT('',(-93.9998,3.24384839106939,-1.31445715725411));
#967=B_SPLINE_CURVE_WITH_KNOTS('',3,(#955,#956,#957,#958,#959,#960,#961,#962,#963,#964,#965,
#966),.UNSPECIFIED.,.F.,.F.,(4,2,2,2,2,4),(0.,0.804796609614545,1.60959181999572,
3.21917489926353,4.70755207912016,6.19593556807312),.UNSPECIFIED.);
#968=CARTESIAN_POINT('',(-100.,1.73205080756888,-0.999999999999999));
#969=VERTEX_POINT('',#968);
#970=EDGE_CURVE('E262',#969,#913,#967,.T.);
#971=ORIENTED_EDGE('',*,*,#970,.F.);
#972=CARTESIAN_POINT('',(-100.,1.73205080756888,1.));
#973=VERTEX_POINT('',#972);
#974=EDGE_CURVE('E336',#969,#973,#157,.T.);
#975=ORIENTED_EDGE('',*,*,#974,.T.);
#976=CARTESIAN_POINT('',(-93.9998,3.24384839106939,1.31445715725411));
#977=CARTESIAN_POINT('',(-94.5002347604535,3.11946254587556,1.2882304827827));
#978=CARTESIAN_POINT('',(-95.000625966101,2.99489977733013,1.26200609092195));
#979=CARTESIAN_POINT('',(-96.0012463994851,2.74513345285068,1.20956579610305));
#980=CARTESIAN_POINT('',(-96.5014756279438,2.61992989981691,1.18334989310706));
#981=CARTESIAN_POINT('',(-97.5017034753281,2.3685935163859,1.13093017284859));
#982=CARTESIAN_POINT('',(-98.0017020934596,2.24246068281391,1.10472635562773));
#983=CARTESIAN_POINT('',(-98.7514105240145,2.05211247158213,1.06543580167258));
#984=CARTESIAN_POINT('',(-99.0012656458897,1.98847143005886,1.0523414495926));
#985=CARTESIAN_POINT('',(-99.5008423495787,1.86066442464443,1.02615974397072));
#986=CARTESIAN_POINT('',(-99.750563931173,1.79649845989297,1.01307239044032));
#987=CARTESIAN_POINT('',(-100.0002,1.73199912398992,0.999989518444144));
#988=B_SPLINE_CURVE_WITH_KNOTS('',3,(#976,#977,#978,#979,#980,#981,#982,#983,#984,#985,#986,
#987),.UNSPECIFIED.,.F.,.F.,(4,2,2,2,2,4),(0.,1.54898444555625,3.09796188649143,
4.64694462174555,5.42143947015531,6.19593558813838),.UNSPECIFIED.);
#989=EDGE_CURVE('E235',#917,#973,#988,.T.);
#990=ORIENTED_EDGE('',*,*,#989,.F.);
#991=ORIENTED_EDGE('',*,*,#918,.F.);
#992=EDGE_LOOP('',(#971,#975,#990,#991));
#993=FACE_BOUND('',#992,.T.);
#994=ADVANCED_FACE('F210',(#993),#117,.T.);
#995=CARTESIAN_POINT('',(-100.,2.,0.));
#996=DIRECTION('',(-1.,0.,0.));
#997=DIRECTION('',(0.,-1.,0.));
#998=AXIS2_PLACEMENT_3D('',#995,#996,#997);
#999=PLANE('',#998);
#1000=DIRECTION('',(0.,1.,0.));
#1001=VECTOR('',#1000,1.);
#1002=CARTESIAN_POINT('',(-100.,2.,-0.999999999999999));
#1003=LINE('',#1002,#1001);
#1004=EDGE_CURVE('E11',#132,#969,#1003,.T.);
#1005=ORIENTED_EDGE('',*,*,#1004,.F.);
#1006=ORIENTED_EDGE('',*,*,#158,.F.);
#1007=DIRECTION('',(0.,-1.,0.));
#1008=VECTOR('',#1007,1.);
#1009=CARTESIAN_POINT('',(-100.,2.,1.));
#1010=LINE('',#1009,#1008);
#1011=EDGE_CURVE('E47',#973,#150,#1010,.T.);
#1012=ORIENTED_EDGE('',*,*,#1011,.F.);
#1013=ORIENTED_EDGE('',*,*,#974,.F.);
#1014=EDGE_LOOP('',(#1005,#1006,#1012,#1013));
#1015=FACE_BOUND('',#1014,.T.);
#1016=ADVANCED_FACE('F321',(#1015),#999,.T.);
#1017=CARTESIAN_POINT('',(-50.,-10.5,5.50000000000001));
#1018=DIRECTION('',(0.,0.,-1.));
#1019=DIRECTION('',(-1.,0.,0.));
#1020=AXIS2_PLACEMENT_3D('',#1017,#1018,#1019);
#1021=PLANE('',#1020);
#1022=DIRECTION('',(-1.,0.,0.));
#1023=VECTOR('',#1022,1.);
#1024=CARTESIAN_POINT('',(-22.5,6.5,5.50000000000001));
#1025=LINE('',#1024,#1023);
#1026=CARTESIAN_POINT('',(-7.50000000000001,6.5,5.50000000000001));
#1027=VERTEX_POINT('',#1026);
#1028=CARTESIAN_POINT('',(-22.5,6.5,5.50000000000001));
#1029=VERTEX_POINT('',#1028);
#1030=EDGE_CURVE('E186',#1027,#1029,#1025,.T.);
#1031=ORIENTED_EDGE('',*,*,#1030,.F.);
#1032=DIRECTION('',(0.,1.,0.));
#1033=VECTOR('',#1032,1.);
#1034=CARTESIAN_POINT('',(-7.50000000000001,6.5,5.50000000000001));
#1035=LINE('',#1034,#1033);
#1036=CARTESIAN_POINT('',(-7.5,-6.5,5.50000000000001));
#1037=VERTEX_POINT('',#1036);
#1038=EDGE_CURVE('E54',#1037,#1027,#1035,.T.);
#1039=ORIENTED_EDGE('',*,*,#1038,.F.);
#1040=DIRECTION('',(1.,0.,0.));
#1041=VECTOR('',#1040,1.);
#1042=CARTESIAN_POINT('',(-22.5,-6.5,5.50000000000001));
#1043=LINE('',#1042,#1041);
#1044=CARTESIAN_POINT('',(-22.5,-6.5,5.50000000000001));
#1045=VERTEX_POINT('',#1044);
#1046=EDGE_CURVE('E177',#1045,#1037,#1043,.T.);
#1047=ORIENTED_EDGE('',*,*,#1046,.F.);
#1048=DIRECTION('',(0.,-1.,0.));
#1049=VECTOR('',#1048,1.);
#1050=CARTESIAN_POINT('',(-22.5,6.5,5.50000000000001));
#1051=LINE('',#1050,#1049);
#1052=EDGE_CURVE('E180',#1029,#1045,#1051,.T.);
#1053=ORIENTED_EDGE('',*,*,#1052,.F.);
#1054=EDGE_LOOP('',(#1031,#1039,#1047,#1053));
#1055=FACE_BOUND('',#1054,.T.);
#1056=CARTESIAN_POINT('',(-5.,0.,5.50000000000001));
#1057=DIRECTION('',(0.,0.,1.));
#1058=DIRECTION('',(1.,0.,0.));
#1059=AXIS2_PLACEMENT_3D('',#1056,#1057,#1058);
#1060=CIRCLE('',#1059,2.);
#1061=CARTESIAN_POINT('',(-3.,0.,5.50000000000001));
#1062=VERTEX_POINT('',#1061);
#1063=EDGE_CURVE('E278',#1062,#1062,#1060,.T.);
#1064=ORIENTED_EDGE('',*,*,#1063,.F.);
#1065=EDGE_LOOP('',(#1064));
#1066=FACE_BOUND('',#1065,.T.);
#1067=ORIENTED_EDGE('',*,*,#802,.T.);
#1068=ORIENTED_EDGE('',*,*,#832,.T.);
#1069=ORIENTED_EDGE('',*,*,#811,.T.);
#1070=ORIENTED_EDGE('',*,*,#779,.T.);
#1071=ORIENTED_EDGE('',*,*,#751,.T.);
#1072=ORIENTED_EDGE('',*,*,#719,.T.);
#1073=ORIENTED_EDGE('',*,*,#448,.T.);
#1074=ORIENTED_EDGE('',*,*,#229,.T.);
#1075=ORIENTED_EDGE('',*,*,#459,.T.);
#1076=ORIENTED_EDGE('',*,*,#593,.T.);
#1077=ORIENTED_EDGE('',*,*,#742,.T.);
#1078=ORIENTED_EDGE('',*,*,#774,.T.);
#1079=EDGE_LOOP('',(#1067,#1068,#1069,#1070,#1071,#1072,#1073,#1074,#1075,#1076,#1077,#1078));
#1080=FACE_BOUND('',#1079,.T.);
#1081=ADVANCED_FACE('F318',(#1055,#1066,#1080),#1021,.F.);
#1082=CARTESIAN_POINT('',(-5.,0.,-10.5));
#1083=DIRECTION('',(0.,0.,1.));
#1084=DIRECTION('',(1.,0.,0.));
#1085=AXIS2_PLACEMENT_3D('',#1082,#1083,#1084);
#1086=CYLINDRICAL_SURFACE('',#1085,2.);
#1087=ORIENTED_EDGE('',*,*,#211,.T.);
#1088=ORIENTED_EDGE('',*,*,#284,.T.);
#1089=EDGE_LOOP('',(#1087,#1088));
#1090=FACE_BOUND('',#1089,.T.);
#1091=ORIENTED_EDGE('',*,*,#1063,.T.);
#1092=EDGE_LOOP('',(#1091));
#1093=FACE_BOUND('',#1092,.T.);
#1094=ADVANCED_FACE('F219',(#1090,#1093),#1086,.F.);
#1095=CARTESIAN_POINT('',(-100.,-10.5,1.));
#1096=DIRECTION('',(0.0523359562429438,0.,-0.998629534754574));
#1097=DIRECTION('',(-0.998629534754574,0.,-0.0523359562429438));
#1098=AXIS2_PLACEMENT_3D('',#1095,#1096,#1097);
#1099=PLANE('',#1098);
#1100=ORIENTED_EDGE('',*,*,#989,.T.);
#1101=ORIENTED_EDGE('',*,*,#1011,.T.);
#1102=ORIENTED_EDGE('',*,*,#151,.T.);
#1103=ORIENTED_EDGE('',*,*,#101,.T.);
#1104=ORIENTED_EDGE('',*,*,#872,.T.);
#1105=ORIENTED_EDGE('',*,*,#949,.T.);
#1106=EDGE_LOOP('',(#1100,#1101,#1102,#1103,#1104,#1105));
#1107=FACE_BOUND('',#1106,.T.);
#1108=ADVANCED_FACE('F213',(#1107),#1099,.F.);
#1109=CARTESIAN_POINT('',(-100.,-10.5,-0.999999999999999));
#1110=DIRECTION('',(0.0523359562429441,0.,0.998629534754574));
#1111=DIRECTION('',(0.998629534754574,0.,-0.0523359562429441));
#1112=AXIS2_PLACEMENT_3D('',#1109,#1110,#1111);
#1113=PLANE('',#1112);
#1114=ORIENTED_EDGE('',*,*,#133,.T.);
#1115=ORIENTED_EDGE('',*,*,#1004,.T.);
#1116=ORIENTED_EDGE('',*,*,#970,.T.);
#1117=ORIENTED_EDGE('',*,*,#914,.T.);
#1118=ORIENTED_EDGE('',*,*,#861,.T.);
#1119=ORIENTED_EDGE('',*,*,#57,.T.);
#1120=EDGE_LOOP('',(#1114,#1115,#1116,#1117,#1118,#1119));
#1121=FACE_BOUND('',#1120,.T.);
#1122=ADVANCED_FACE('F218',(#1121),#1113,.F.);
#1123=CARTESIAN_POINT('',(-7.50000000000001,6.5,4.50000000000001));
#1124=DIRECTION('',(1.,0.,0.));
#1125=DIRECTION('',(0.,1.,0.));
#1126=AXIS2_PLACEMENT_3D('',#1123,#1124,#1125);
#1127=PLANE('',#1126);
#1128=ORIENTED_EDGE('',*,*,#1038,.T.);
#1129=DIRECTION('',(0.,0.,1.));
#1130=VECTOR('',#1129,1.);
#1131=CARTESIAN_POINT('',(-7.50000000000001,6.5,4.50000000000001));
#1132=LINE('',#1131,#1130);
#1133=CARTESIAN_POINT('',(-7.50000000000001,6.5,4.50000000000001));
#1134=VERTEX_POINT('',#1133);
#1135=EDGE_CURVE('E155',#1134,#1027,#1132,.T.);
#1136=ORIENTED_EDGE('',*,*,#1135,.F.);
#1137=DIRECTION('',(0.,1.,0.));
#1138=VECTOR('',#1137,1.);
#1139=CARTESIAN_POINT('',(-7.50000000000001,6.5,4.50000000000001));
#1140=LINE('',#1139,#1138);
#1141=CARTESIAN_POINT('',(-7.5,-6.5,4.50000000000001));
#1142=VERTEX_POINT('',#1141);
#1143=EDGE_CURVE('E159',#1142,#1134,#1140,.T.);
#1144=ORIENTED_EDGE('',*,*,#1143,.F.);
#1145=DIRECTION('',(0.,0.,1.));
#1146=VECTOR('',#1145,1.);
#1147=CARTESIAN_POINT('',(-7.5,-6.5,4.50000000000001));
#1148=LINE('',#1147,#1146);
#1149=EDGE_CURVE('E190',#1142,#1037,#1148,.T.);
#1150=ORIENTED_EDGE('',*,*,#1149,.T.);
#1151=EDGE_LOOP('',(#1128,#1136,#1144,#1150));
#1152=FACE_BOUND('',#1151,.T.);
#1153=ADVANCED_FACE('F157',(#1152),#1127,.F.);
#1154=CARTESIAN_POINT('',(-22.5,-6.5,4.50000000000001));
#1155=DIRECTION('',(0.,-1.,0.));
#1156=DIRECTION('',(0.,0.,-1.));
#1157=AXIS2_PLACEMENT_3D('',#1154,#1155,#1156);
#1158=PLANE('',#1157);
#1159=ORIENTED_EDGE('',*,*,#1046,.T.);
#1160=ORIENTED_EDGE('',*,*,#1149,.F.);
#1161=DIRECTION('',(1.,0.,0.));
#1162=VECTOR('',#1161,1.);
#1163=CARTESIAN_POINT('',(-22.5,-6.5,4.50000000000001));
#1164=LINE('',#1163,#1162);
#1165=CARTESIAN_POINT('',(-22.5,-6.5,4.50000000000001));
#1166=VERTEX_POINT('',#1165);
#1167=EDGE_CURVE('E165',#1166,#1142,#1164,.T.);
#1168=ORIENTED_EDGE('',*,*,#1167,.F.);
#1169=DIRECTION('',(0.,0.,1.));
#1170=VECTOR('',#1169,1.);
#1171=CARTESIAN_POINT('',(-22.5,-6.5,4.50000000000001));
#1172=LINE('',#1171,#1170);
#1173=EDGE_CURVE('E193',#1166,#1045,#1172,.T.);
#1174=ORIENTED_EDGE('',*,*,#1173,.T.);
#1175=EDGE_LOOP('',(#1159,#1160,#1168,#1174));
#1176=FACE_BOUND('',#1175,.T.);
#1177=ADVANCED_FACE('F452',(#1176),#1158,.F.);
#1178=CARTESIAN_POINT('',(-22.5,6.5,4.50000000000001));
#1179=DIRECTION('',(-1.,0.,0.));
#1180=DIRECTION('',(0.,0.,1.));
#1181=AXIS2_PLACEMENT_3D('',#1178,#1179,#1180);
#1182=PLANE('',#1181);
#1183=ORIENTED_EDGE('',*,*,#1052,.T.);
#1184=ORIENTED_EDGE('',*,*,#1173,.F.);
#1185=DIRECTION('',(0.,-1.,0.));
#1186=VECTOR('',#1185,1.);
#1187=CARTESIAN_POINT('',(-22.5,6.5,4.50000000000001));
#1188=LINE('',#1187,#1186);
#1189=CARTESIAN_POINT('',(-22.5,6.5,4.50000000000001));
#1190=VERTEX_POINT('',#1189);
#1191=EDGE_CURVE('E173',#1190,#1166,#1188,.T.);
#1192=ORIENTED_EDGE('',*,*,#1191,.F.);
#1193=DIRECTION('',(0.,0.,1.));
#1194=VECTOR('',#1193,1.);
#1195=CARTESIAN_POINT('',(-22.5,6.5,4.50000000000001));
#1196=LINE('',#1195,#1194);
#1197=EDGE_CURVE('E164',#1190,#1029,#1196,.T.);
#1198=ORIENTED_EDGE('',*,*,#1197,.T.);
#1199=EDGE_LOOP('',(#1183,#1184,#1192,#1198));
#1200=FACE_BOUND('',#1199,.T.);
#1201=ADVANCED_FACE('F458',(#1200),#1182,.F.);
#1202=CARTESIAN_POINT('',(-22.5,6.5,4.50000000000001));
#1203=DIRECTION('',(0.,1.,0.));
#1204=DIRECTION('',(0.,0.,1.));
#1205=AXIS2_PLACEMENT_3D('',#1202,#1203,#1204);
#1206=PLANE('',#1205);
#1207=ORIENTED_EDGE('',*,*,#1030,.T.);
#1208=ORIENTED_EDGE('',*,*,#1197,.F.);
#1209=DIRECTION('',(-1.,0.,0.));
#1210=VECTOR('',#1209,1.);
#1211=CARTESIAN_POINT('',(-22.5,6.5,4.50000000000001));
#1212=LINE('',#1211,#1210);
#1213=EDGE_CURVE('E168',#1134,#1190,#1212,.T.);
#1214=ORIENTED_EDGE('',*,*,#1213,.F.);
#1215=ORIENTED_EDGE('',*,*,#1135,.T.);
#1216=EDGE_LOOP('',(#1207,#1208,#1214,#1215));
#1217=FACE_BOUND('',#1216,.T.);
#1218=ADVANCED_FACE('F169',(#1217),#1206,.F.);
#1219=CARTESIAN_POINT('',(0.,0.,4.50000000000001));
#1220=DIRECTION('',(0.,0.,1.));
#1221=DIRECTION('',(1.,0.,0.));
#1222=AXIS2_PLACEMENT_3D('',#1219,#1220,#1221);
#1223=PLANE('',#1222);
#1224=ORIENTED_EDGE('',*,*,#1143,.T.);
#1225=ORIENTED_EDGE('',*,*,#1213,.T.);
#1226=ORIENTED_EDGE('',*,*,#1191,.T.);
#1227=ORIENTED_EDGE('',*,*,#1167,.T.);
#1228=EDGE_LOOP('',(#1224,#1225,#1226,#1227));
#1229=FACE_BOUND('',#1228,.T.);
#1230=ADVANCED_FACE('F175',(#1229),#1223,.T.);
#1231=CLOSED_SHELL('',(#112,#162,#235,#464,#730,#762,#790,#822,#848,#880,#954,#994,#1016,#1081,
#1094,#1108,#1122,#1153,#1177,#1201,#1218,#1230));
#1232=MANIFOLD_SOLID_BREP('B2',#1231);
#1233=ADVANCED_BREP_SHAPE_REPRESENTATION('',(#18,#1232),#14);
#1234=SHAPE_DEFINITION_REPRESENTATION(#9,#1233);
ENDSEC;
END-ISO-10303-21;
